VERSION 5.8 ;
BUSBITCHARS "[]" ;
DIVIDERCHAR "/" ;
UNITS
    DATABASE MICRONS 1000 ;
END UNITS

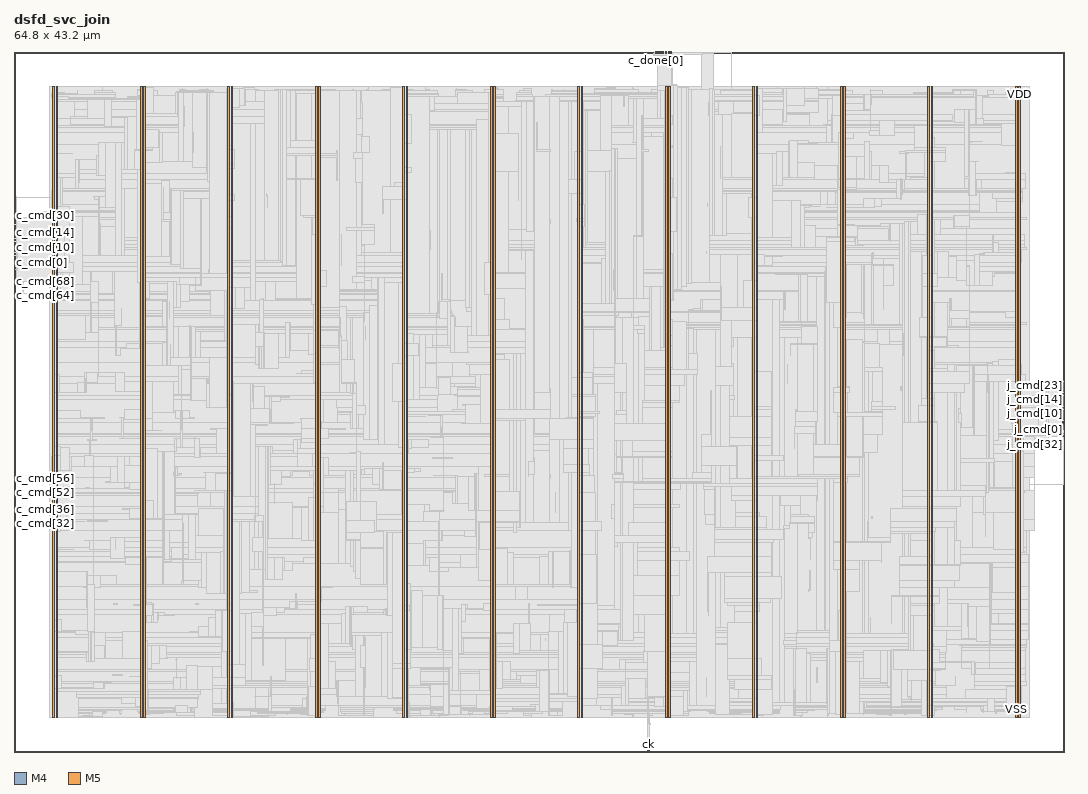
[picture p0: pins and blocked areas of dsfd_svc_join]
MACRO dsfd_svc_join
  FOREIGN dsfd_svc_join 0 0 ;
  CLASS BLOCK ;
  SIZE 64.8 BY 43.2 ;
  PIN c_cmd[0]
    DIRECTION INPUT ;
    USE SIGNAL ;
    PORT
      LAYER M4 ;
        RECT  0 30.192 0.084 30.216 ;
    END
  END c_cmd[0]
  PIN c_cmd[10]
    DIRECTION INPUT ;
    USE SIGNAL ;
    PORT
      LAYER M4 ;
        RECT  0 31.152 0.084 31.176 ;
    END
  END c_cmd[10]
  PIN c_cmd[11]
    DIRECTION INPUT ;
    USE SIGNAL ;
    PORT
      LAYER M4 ;
        RECT  0 31.248 0.084 31.272 ;
    END
  END c_cmd[11]
  PIN c_cmd[12]
    DIRECTION INPUT ;
    USE SIGNAL ;
    PORT
      LAYER M4 ;
        RECT  0 31.344 0.084 31.368 ;
    END
  END c_cmd[12]
  PIN c_cmd[13]
    DIRECTION INPUT ;
    USE SIGNAL ;
    PORT
      LAYER M4 ;
        RECT  0 31.44 0.084 31.464 ;
    END
  END c_cmd[13]
  PIN c_cmd[14]
    DIRECTION INPUT ;
    USE SIGNAL ;
    PORT
      LAYER M4 ;
        RECT  0 31.536 0.084 31.56 ;
    END
  END c_cmd[14]
  PIN c_cmd[15]
    DIRECTION INPUT ;
    USE SIGNAL ;
    PORT
      LAYER M4 ;
        RECT  0 31.632 0.084 31.656 ;
    END
  END c_cmd[15]
  PIN c_cmd[16]
    DIRECTION INPUT ;
    USE SIGNAL ;
    PORT
      LAYER M4 ;
        RECT  0 31.728 0.084 31.752 ;
    END
  END c_cmd[16]
  PIN c_cmd[17]
    DIRECTION INPUT ;
    USE SIGNAL ;
    PORT
      LAYER M4 ;
        RECT  0 31.824 0.084 31.848 ;
    END
  END c_cmd[17]
  PIN c_cmd[18]
    DIRECTION INPUT ;
    USE SIGNAL ;
    PORT
      LAYER M4 ;
        RECT  0 31.92 0.084 31.944 ;
    END
  END c_cmd[18]
  PIN c_cmd[19]
    DIRECTION INPUT ;
    USE SIGNAL ;
    PORT
      LAYER M4 ;
        RECT  0 32.016 0.084 32.04 ;
    END
  END c_cmd[19]
  PIN c_cmd[1]
    DIRECTION INPUT ;
    USE SIGNAL ;
    PORT
      LAYER M4 ;
        RECT  0 30.288 0.084 30.312 ;
    END
  END c_cmd[1]
  PIN c_cmd[20]
    DIRECTION INPUT ;
    USE SIGNAL ;
    PORT
      LAYER M4 ;
        RECT  0 32.112 0.084 32.136 ;
    END
  END c_cmd[20]
  PIN c_cmd[21]
    DIRECTION INPUT ;
    USE SIGNAL ;
    PORT
      LAYER M4 ;
        RECT  0 32.208 0.084 32.232 ;
    END
  END c_cmd[21]
  PIN c_cmd[22]
    DIRECTION INPUT ;
    USE SIGNAL ;
    PORT
      LAYER M4 ;
        RECT  0 32.304 0.084 32.328 ;
    END
  END c_cmd[22]
  PIN c_cmd[23]
    DIRECTION INPUT ;
    USE SIGNAL ;
    PORT
      LAYER M4 ;
        RECT  0 32.4 0.084 32.424 ;
    END
  END c_cmd[23]
  PIN c_cmd[24]
    DIRECTION INPUT ;
    USE SIGNAL ;
    PORT
      LAYER M4 ;
        RECT  0 32.496 0.084 32.52 ;
    END
  END c_cmd[24]
  PIN c_cmd[25]
    DIRECTION INPUT ;
    USE SIGNAL ;
    PORT
      LAYER M4 ;
        RECT  0 32.592 0.084 32.616 ;
    END
  END c_cmd[25]
  PIN c_cmd[26]
    DIRECTION INPUT ;
    USE SIGNAL ;
    PORT
      LAYER M4 ;
        RECT  0 32.688 0.084 32.712 ;
    END
  END c_cmd[26]
  PIN c_cmd[27]
    DIRECTION INPUT ;
    USE SIGNAL ;
    PORT
      LAYER M4 ;
        RECT  0 32.784 0.084 32.808 ;
    END
  END c_cmd[27]
  PIN c_cmd[28]
    DIRECTION INPUT ;
    USE SIGNAL ;
    PORT
      LAYER M4 ;
        RECT  0 32.88 0.084 32.904 ;
    END
  END c_cmd[28]
  PIN c_cmd[29]
    DIRECTION INPUT ;
    USE SIGNAL ;
    PORT
      LAYER M4 ;
        RECT  0 32.976 0.084 33 ;
    END
  END c_cmd[29]
  PIN c_cmd[2]
    DIRECTION INPUT ;
    USE SIGNAL ;
    PORT
      LAYER M4 ;
        RECT  0 30.384 0.084 30.408 ;
    END
  END c_cmd[2]
  PIN c_cmd[30]
    DIRECTION INPUT ;
    USE SIGNAL ;
    PORT
      LAYER M4 ;
        RECT  0 33.072 0.084 33.096 ;
    END
  END c_cmd[30]
  PIN c_cmd[31]
    DIRECTION INPUT ;
    USE SIGNAL ;
    PORT
      LAYER M4 ;
        RECT  0 33.168 0.084 33.192 ;
    END
  END c_cmd[31]
  PIN c_cmd[32]
    DIRECTION INPUT ;
    USE SIGNAL ;
    PORT
      LAYER M4 ;
        RECT  0 14.064 0.084 14.088 ;
    END
  END c_cmd[32]
  PIN c_cmd[33]
    DIRECTION INPUT ;
    USE SIGNAL ;
    PORT
      LAYER M4 ;
        RECT  0 14.16 0.084 14.184 ;
    END
  END c_cmd[33]
  PIN c_cmd[34]
    DIRECTION INPUT ;
    USE SIGNAL ;
    PORT
      LAYER M4 ;
        RECT  0 14.256 0.084 14.28 ;
    END
  END c_cmd[34]
  PIN c_cmd[35]
    DIRECTION INPUT ;
    USE SIGNAL ;
    PORT
      LAYER M4 ;
        RECT  0 14.352 0.084 14.376 ;
    END
  END c_cmd[35]
  PIN c_cmd[36]
    DIRECTION INPUT ;
    USE SIGNAL ;
    PORT
      LAYER M4 ;
        RECT  0 14.448 0.084 14.472 ;
    END
  END c_cmd[36]
  PIN c_cmd[37]
    DIRECTION INPUT ;
    USE SIGNAL ;
    PORT
      LAYER M4 ;
        RECT  0 14.544 0.084 14.568 ;
    END
  END c_cmd[37]
  PIN c_cmd[38]
    DIRECTION INPUT ;
    USE SIGNAL ;
    PORT
      LAYER M4 ;
        RECT  0 14.64 0.084 14.664 ;
    END
  END c_cmd[38]
  PIN c_cmd[39]
    DIRECTION INPUT ;
    USE SIGNAL ;
    PORT
      LAYER M4 ;
        RECT  0 14.736 0.084 14.76 ;
    END
  END c_cmd[39]
  PIN c_cmd[3]
    DIRECTION INPUT ;
    USE SIGNAL ;
    PORT
      LAYER M4 ;
        RECT  0 30.48 0.084 30.504 ;
    END
  END c_cmd[3]
  PIN c_cmd[40]
    DIRECTION INPUT ;
    USE SIGNAL ;
    PORT
      LAYER M4 ;
        RECT  0 14.832 0.084 14.856 ;
    END
  END c_cmd[40]
  PIN c_cmd[41]
    DIRECTION INPUT ;
    USE SIGNAL ;
    PORT
      LAYER M4 ;
        RECT  0 14.928 0.084 14.952 ;
    END
  END c_cmd[41]
  PIN c_cmd[42]
    DIRECTION INPUT ;
    USE SIGNAL ;
    PORT
      LAYER M4 ;
        RECT  0 15.024 0.084 15.048 ;
    END
  END c_cmd[42]
  PIN c_cmd[43]
    DIRECTION INPUT ;
    USE SIGNAL ;
    PORT
      LAYER M4 ;
        RECT  0 15.12 0.084 15.144 ;
    END
  END c_cmd[43]
  PIN c_cmd[44]
    DIRECTION INPUT ;
    USE SIGNAL ;
    PORT
      LAYER M4 ;
        RECT  0 15.216 0.084 15.24 ;
    END
  END c_cmd[44]
  PIN c_cmd[45]
    DIRECTION INPUT ;
    USE SIGNAL ;
    PORT
      LAYER M4 ;
        RECT  0 15.312 0.084 15.336 ;
    END
  END c_cmd[45]
  PIN c_cmd[46]
    DIRECTION INPUT ;
    USE SIGNAL ;
    PORT
      LAYER M4 ;
        RECT  0 15.408 0.084 15.432 ;
    END
  END c_cmd[46]
  PIN c_cmd[47]
    DIRECTION INPUT ;
    USE SIGNAL ;
    PORT
      LAYER M4 ;
        RECT  0 15.504 0.084 15.528 ;
    END
  END c_cmd[47]
  PIN c_cmd[48]
    DIRECTION INPUT ;
    USE SIGNAL ;
    PORT
      LAYER M4 ;
        RECT  0 15.6 0.084 15.624 ;
    END
  END c_cmd[48]
  PIN c_cmd[49]
    DIRECTION INPUT ;
    USE SIGNAL ;
    PORT
      LAYER M4 ;
        RECT  0 15.696 0.084 15.72 ;
    END
  END c_cmd[49]
  PIN c_cmd[4]
    DIRECTION INPUT ;
    USE SIGNAL ;
    PORT
      LAYER M4 ;
        RECT  0 30.576 0.084 30.6 ;
    END
  END c_cmd[4]
  PIN c_cmd[50]
    DIRECTION INPUT ;
    USE SIGNAL ;
    PORT
      LAYER M4 ;
        RECT  0 15.792 0.084 15.816 ;
    END
  END c_cmd[50]
  PIN c_cmd[51]
    DIRECTION INPUT ;
    USE SIGNAL ;
    PORT
      LAYER M4 ;
        RECT  0 15.888 0.084 15.912 ;
    END
  END c_cmd[51]
  PIN c_cmd[52]
    DIRECTION INPUT ;
    USE SIGNAL ;
    PORT
      LAYER M4 ;
        RECT  0 15.984 0.084 16.008 ;
    END
  END c_cmd[52]
  PIN c_cmd[53]
    DIRECTION INPUT ;
    USE SIGNAL ;
    PORT
      LAYER M4 ;
        RECT  0 16.08 0.084 16.104 ;
    END
  END c_cmd[53]
  PIN c_cmd[54]
    DIRECTION INPUT ;
    USE SIGNAL ;
    PORT
      LAYER M4 ;
        RECT  0 16.176 0.084 16.2 ;
    END
  END c_cmd[54]
  PIN c_cmd[55]
    DIRECTION INPUT ;
    USE SIGNAL ;
    PORT
      LAYER M4 ;
        RECT  0 16.272 0.084 16.296 ;
    END
  END c_cmd[55]
  PIN c_cmd[56]
    DIRECTION INPUT ;
    USE SIGNAL ;
    PORT
      LAYER M4 ;
        RECT  0 16.368 0.084 16.392 ;
    END
  END c_cmd[56]
  PIN c_cmd[57]
    DIRECTION INPUT ;
    USE SIGNAL ;
    PORT
      LAYER M4 ;
        RECT  0 16.464 0.084 16.488 ;
    END
  END c_cmd[57]
  PIN c_cmd[58]
    DIRECTION INPUT ;
    USE SIGNAL ;
    PORT
      LAYER M4 ;
        RECT  0 16.56 0.084 16.584 ;
    END
  END c_cmd[58]
  PIN c_cmd[59]
    DIRECTION INPUT ;
    USE SIGNAL ;
    PORT
      LAYER M4 ;
        RECT  0 16.656 0.084 16.68 ;
    END
  END c_cmd[59]
  PIN c_cmd[5]
    DIRECTION INPUT ;
    USE SIGNAL ;
    PORT
      LAYER M4 ;
        RECT  0 30.672 0.084 30.696 ;
    END
  END c_cmd[5]
  PIN c_cmd[60]
    DIRECTION INPUT ;
    USE SIGNAL ;
    PORT
      LAYER M4 ;
        RECT  0 16.752 0.084 16.776 ;
    END
  END c_cmd[60]
  PIN c_cmd[61]
    DIRECTION INPUT ;
    USE SIGNAL ;
    PORT
      LAYER M4 ;
        RECT  0 16.848 0.084 16.872 ;
    END
  END c_cmd[61]
  PIN c_cmd[62]
    DIRECTION INPUT ;
    USE SIGNAL ;
    PORT
      LAYER M4 ;
        RECT  0 16.944 0.084 16.968 ;
    END
  END c_cmd[62]
  PIN c_cmd[63]
    DIRECTION INPUT ;
    USE SIGNAL ;
    PORT
      LAYER M4 ;
        RECT  0 17.04 0.084 17.064 ;
    END
  END c_cmd[63]
  PIN c_cmd[64]
    DIRECTION INPUT ;
    USE SIGNAL ;
    PORT
      LAYER M4 ;
        RECT  0 28.176 0.084 28.2 ;
    END
  END c_cmd[64]
  PIN c_cmd[65]
    DIRECTION INPUT ;
    USE SIGNAL ;
    PORT
      LAYER M4 ;
        RECT  0 28.272 0.084 28.296 ;
    END
  END c_cmd[65]
  PIN c_cmd[66]
    DIRECTION INPUT ;
    USE SIGNAL ;
    PORT
      LAYER M4 ;
        RECT  0 28.368 0.084 28.392 ;
    END
  END c_cmd[66]
  PIN c_cmd[67]
    DIRECTION INPUT ;
    USE SIGNAL ;
    PORT
      LAYER M4 ;
        RECT  0 28.464 0.084 28.488 ;
    END
  END c_cmd[67]
  PIN c_cmd[68]
    DIRECTION INPUT ;
    USE SIGNAL ;
    PORT
      LAYER M4 ;
        RECT  0 28.56 0.084 28.584 ;
    END
  END c_cmd[68]
  PIN c_cmd[69]
    DIRECTION INPUT ;
    USE SIGNAL ;
    PORT
      LAYER M4 ;
        RECT  0 28.656 0.084 28.68 ;
    END
  END c_cmd[69]
  PIN c_cmd[6]
    DIRECTION INPUT ;
    USE SIGNAL ;
    PORT
      LAYER M4 ;
        RECT  0 30.768 0.084 30.792 ;
    END
  END c_cmd[6]
  PIN c_cmd[70]
    DIRECTION INPUT ;
    USE SIGNAL ;
    PORT
      LAYER M4 ;
        RECT  0 28.752 0.084 28.776 ;
    END
  END c_cmd[70]
  PIN c_cmd[71]
    DIRECTION INPUT ;
    USE SIGNAL ;
    PORT
      LAYER M4 ;
        RECT  0 28.848 0.084 28.872 ;
    END
  END c_cmd[71]
  PIN c_cmd[72]
    DIRECTION INPUT ;
    USE SIGNAL ;
    PORT
      LAYER M4 ;
        RECT  0 28.944 0.084 28.968 ;
    END
  END c_cmd[72]
  PIN c_cmd[73]
    DIRECTION INPUT ;
    USE SIGNAL ;
    PORT
      LAYER M4 ;
        RECT  0 29.04 0.084 29.064 ;
    END
  END c_cmd[73]
  PIN c_cmd[74]
    DIRECTION INPUT ;
    USE SIGNAL ;
    PORT
      LAYER M4 ;
        RECT  0 29.136 0.084 29.16 ;
    END
  END c_cmd[74]
  PIN c_cmd[75]
    DIRECTION INPUT ;
    USE SIGNAL ;
    PORT
      LAYER M4 ;
        RECT  0 29.232 0.084 29.256 ;
    END
  END c_cmd[75]
  PIN c_cmd[76]
    DIRECTION INPUT ;
    USE SIGNAL ;
    PORT
      LAYER M4 ;
        RECT  0 29.328 0.084 29.352 ;
    END
  END c_cmd[76]
  PIN c_cmd[77]
    DIRECTION INPUT ;
    USE SIGNAL ;
    PORT
      LAYER M4 ;
        RECT  0 29.424 0.084 29.448 ;
    END
  END c_cmd[77]
  PIN c_cmd[78]
    DIRECTION INPUT ;
    USE SIGNAL ;
    PORT
      LAYER M4 ;
        RECT  0 29.52 0.084 29.544 ;
    END
  END c_cmd[78]
  PIN c_cmd[79]
    DIRECTION INPUT ;
    USE SIGNAL ;
    PORT
      LAYER M4 ;
        RECT  0 29.616 0.084 29.64 ;
    END
  END c_cmd[79]
  PIN c_cmd[7]
    DIRECTION INPUT ;
    USE SIGNAL ;
    PORT
      LAYER M4 ;
        RECT  0 30.864 0.084 30.888 ;
    END
  END c_cmd[7]
  PIN c_cmd[80]
    DIRECTION INPUT ;
    USE SIGNAL ;
    PORT
      LAYER M4 ;
        RECT  0 29.712 0.084 29.736 ;
    END
  END c_cmd[80]
  PIN c_cmd[81]
    DIRECTION INPUT ;
    USE SIGNAL ;
    PORT
      LAYER M4 ;
        RECT  0 29.808 0.084 29.832 ;
    END
  END c_cmd[81]
  PIN c_cmd[82]
    DIRECTION INPUT ;
    USE SIGNAL ;
    PORT
      LAYER M4 ;
        RECT  0 29.904 0.084 29.928 ;
    END
  END c_cmd[82]
  PIN c_cmd[83]
    DIRECTION INPUT ;
    USE SIGNAL ;
    PORT
      LAYER M4 ;
        RECT  0 30 0.084 30.024 ;
    END
  END c_cmd[83]
  PIN c_cmd[84]
    DIRECTION INPUT ;
    USE SIGNAL ;
    PORT
      LAYER M4 ;
        RECT  0 30.096 0.084 30.12 ;
    END
  END c_cmd[84]
  PIN c_cmd[8]
    DIRECTION INPUT ;
    USE SIGNAL ;
    PORT
      LAYER M4 ;
        RECT  0 30.96 0.084 30.984 ;
    END
  END c_cmd[8]
  PIN c_cmd[9]
    DIRECTION INPUT ;
    USE SIGNAL ;
    PORT
      LAYER M4 ;
        RECT  0 31.056 0.084 31.08 ;
    END
  END c_cmd[9]
  PIN c_done[0]
    DIRECTION OUTPUT ;
    USE SIGNAL ;
    PORT
      LAYER M5 ;
        RECT  39.6 43.116 39.624 43.2 ;
    END
  END c_done[0]
  PIN c_done[1]
    DIRECTION OUTPUT ;
    USE SIGNAL ;
    PORT
      LAYER M5 ;
        RECT  39.696 43.116 39.72 43.2 ;
    END
  END c_done[1]
  PIN c_done[2]
    DIRECTION OUTPUT ;
    USE SIGNAL ;
    PORT
      LAYER M5 ;
        RECT  39.792 43.116 39.816 43.2 ;
    END
  END c_done[2]
  PIN c_done[3]
    DIRECTION OUTPUT ;
    USE SIGNAL ;
    PORT
      LAYER M5 ;
        RECT  39.888 43.116 39.912 43.2 ;
    END
  END c_done[3]
  PIN c_done[4]
    DIRECTION OUTPUT ;
    USE SIGNAL ;
    PORT
      LAYER M5 ;
        RECT  39.984 43.116 40.008 43.2 ;
    END
  END c_done[4]
  PIN c_done[5]
    DIRECTION OUTPUT ;
    USE SIGNAL ;
    PORT
      LAYER M5 ;
        RECT  40.08 43.116 40.104 43.2 ;
    END
  END c_done[5]
  PIN c_done[6]
    DIRECTION OUTPUT ;
    USE SIGNAL ;
    PORT
      LAYER M5 ;
        RECT  40.176 43.116 40.2 43.2 ;
    END
  END c_done[6]
  PIN c_done[7]
    DIRECTION OUTPUT ;
    USE SIGNAL ;
    PORT
      LAYER M5 ;
        RECT  40.272 43.116 40.296 43.2 ;
    END
  END c_done[7]
  PIN c_done[8]
    DIRECTION OUTPUT ;
    USE SIGNAL ;
    PORT
      LAYER M5 ;
        RECT  40.368 43.116 40.392 43.2 ;
    END
  END c_done[8]
  PIN c_st[0]
    DIRECTION OUTPUT ;
    USE SIGNAL ;
    PORT
      LAYER M5 ;
        RECT  40.464 43.116 40.488 43.2 ;
    END
  END c_st[0]
  PIN c_st[1]
    DIRECTION OUTPUT ;
    USE SIGNAL ;
    PORT
      LAYER M5 ;
        RECT  40.56 43.116 40.584 43.2 ;
    END
  END c_st[1]
  PIN ck
    DIRECTION INPUT ;
    USE SIGNAL ;
    PORT
      LAYER M5 ;
        RECT  39.12 0 39.144 0.084 ;
    END
  END ck
  PIN j_cmd[0]
    DIRECTION OUTPUT ;
    USE SIGNAL ;
    PORT
      LAYER M4 ;
        RECT  64.716 19.92 64.8 19.944 ;
    END
  END j_cmd[0]
  PIN j_cmd[10]
    DIRECTION OUTPUT ;
    USE SIGNAL ;
    PORT
      LAYER M4 ;
        RECT  64.716 20.88 64.8 20.904 ;
    END
  END j_cmd[10]
  PIN j_cmd[11]
    DIRECTION OUTPUT ;
    USE SIGNAL ;
    PORT
      LAYER M4 ;
        RECT  64.716 20.976 64.8 21 ;
    END
  END j_cmd[11]
  PIN j_cmd[12]
    DIRECTION OUTPUT ;
    USE SIGNAL ;
    PORT
      LAYER M4 ;
        RECT  64.716 21.072 64.8 21.096 ;
    END
  END j_cmd[12]
  PIN j_cmd[13]
    DIRECTION OUTPUT ;
    USE SIGNAL ;
    PORT
      LAYER M4 ;
        RECT  64.716 21.168 64.8 21.192 ;
    END
  END j_cmd[13]
  PIN j_cmd[14]
    DIRECTION OUTPUT ;
    USE SIGNAL ;
    PORT
      LAYER M4 ;
        RECT  64.716 21.264 64.8 21.288 ;
    END
  END j_cmd[14]
  PIN j_cmd[15]
    DIRECTION OUTPUT ;
    USE SIGNAL ;
    PORT
      LAYER M4 ;
        RECT  64.716 21.36 64.8 21.384 ;
    END
  END j_cmd[15]
  PIN j_cmd[16]
    DIRECTION OUTPUT ;
    USE SIGNAL ;
    PORT
      LAYER M4 ;
        RECT  64.716 21.456 64.8 21.48 ;
    END
  END j_cmd[16]
  PIN j_cmd[17]
    DIRECTION OUTPUT ;
    USE SIGNAL ;
    PORT
      LAYER M4 ;
        RECT  64.716 21.552 64.8 21.576 ;
    END
  END j_cmd[17]
  PIN j_cmd[18]
    DIRECTION OUTPUT ;
    USE SIGNAL ;
    PORT
      LAYER M4 ;
        RECT  64.716 21.648 64.8 21.672 ;
    END
  END j_cmd[18]
  PIN j_cmd[19]
    DIRECTION OUTPUT ;
    USE SIGNAL ;
    PORT
      LAYER M4 ;
        RECT  64.716 21.744 64.8 21.768 ;
    END
  END j_cmd[19]
  PIN j_cmd[1]
    DIRECTION OUTPUT ;
    USE SIGNAL ;
    PORT
      LAYER M4 ;
        RECT  64.716 20.016 64.8 20.04 ;
    END
  END j_cmd[1]
  PIN j_cmd[20]
    DIRECTION OUTPUT ;
    USE SIGNAL ;
    PORT
      LAYER M4 ;
        RECT  64.716 21.84 64.8 21.864 ;
    END
  END j_cmd[20]
  PIN j_cmd[21]
    DIRECTION OUTPUT ;
    USE SIGNAL ;
    PORT
      LAYER M4 ;
        RECT  64.716 21.936 64.8 21.96 ;
    END
  END j_cmd[21]
  PIN j_cmd[22]
    DIRECTION OUTPUT ;
    USE SIGNAL ;
    PORT
      LAYER M4 ;
        RECT  64.716 22.032 64.8 22.056 ;
    END
  END j_cmd[22]
  PIN j_cmd[23]
    DIRECTION OUTPUT ;
    USE SIGNAL ;
    PORT
      LAYER M4 ;
        RECT  64.716 22.128 64.8 22.152 ;
    END
  END j_cmd[23]
  PIN j_cmd[24]
    DIRECTION OUTPUT ;
    USE SIGNAL ;
    PORT
      LAYER M4 ;
        RECT  64.716 22.224 64.8 22.248 ;
    END
  END j_cmd[24]
  PIN j_cmd[25]
    DIRECTION OUTPUT ;
    USE SIGNAL ;
    PORT
      LAYER M4 ;
        RECT  64.716 22.32 64.8 22.344 ;
    END
  END j_cmd[25]
  PIN j_cmd[26]
    DIRECTION OUTPUT ;
    USE SIGNAL ;
    PORT
      LAYER M4 ;
        RECT  64.716 22.416 64.8 22.44 ;
    END
  END j_cmd[26]
  PIN j_cmd[27]
    DIRECTION OUTPUT ;
    USE SIGNAL ;
    PORT
      LAYER M4 ;
        RECT  64.716 22.512 64.8 22.536 ;
    END
  END j_cmd[27]
  PIN j_cmd[28]
    DIRECTION OUTPUT ;
    USE SIGNAL ;
    PORT
      LAYER M4 ;
        RECT  64.716 22.608 64.8 22.632 ;
    END
  END j_cmd[28]
  PIN j_cmd[29]
    DIRECTION OUTPUT ;
    USE SIGNAL ;
    PORT
      LAYER M4 ;
        RECT  64.716 22.704 64.8 22.728 ;
    END
  END j_cmd[29]
  PIN j_cmd[2]
    DIRECTION OUTPUT ;
    USE SIGNAL ;
    PORT
      LAYER M4 ;
        RECT  64.716 20.112 64.8 20.136 ;
    END
  END j_cmd[2]
  PIN j_cmd[30]
    DIRECTION OUTPUT ;
    USE SIGNAL ;
    PORT
      LAYER M4 ;
        RECT  64.716 22.8 64.8 22.824 ;
    END
  END j_cmd[30]
  PIN j_cmd[31]
    DIRECTION OUTPUT ;
    USE SIGNAL ;
    PORT
      LAYER M4 ;
        RECT  64.716 22.896 64.8 22.92 ;
    END
  END j_cmd[31]
  PIN j_cmd[32]
    DIRECTION OUTPUT ;
    USE SIGNAL ;
    PORT
      LAYER M4 ;
        RECT  64.716 19.44 64.8 19.464 ;
    END
  END j_cmd[32]
  PIN j_cmd[3]
    DIRECTION OUTPUT ;
    USE SIGNAL ;
    PORT
      LAYER M4 ;
        RECT  64.716 20.208 64.8 20.232 ;
    END
  END j_cmd[3]
  PIN j_cmd[4]
    DIRECTION OUTPUT ;
    USE SIGNAL ;
    PORT
      LAYER M4 ;
        RECT  64.716 20.304 64.8 20.328 ;
    END
  END j_cmd[4]
  PIN j_cmd[5]
    DIRECTION OUTPUT ;
    USE SIGNAL ;
    PORT
      LAYER M4 ;
        RECT  64.716 20.4 64.8 20.424 ;
    END
  END j_cmd[5]
  PIN j_cmd[6]
    DIRECTION OUTPUT ;
    USE SIGNAL ;
    PORT
      LAYER M4 ;
        RECT  64.716 20.496 64.8 20.52 ;
    END
  END j_cmd[6]
  PIN j_cmd[7]
    DIRECTION OUTPUT ;
    USE SIGNAL ;
    PORT
      LAYER M4 ;
        RECT  64.716 20.592 64.8 20.616 ;
    END
  END j_cmd[7]
  PIN j_cmd[8]
    DIRECTION OUTPUT ;
    USE SIGNAL ;
    PORT
      LAYER M4 ;
        RECT  64.716 20.688 64.8 20.712 ;
    END
  END j_cmd[8]
  PIN j_cmd[9]
    DIRECTION OUTPUT ;
    USE SIGNAL ;
    PORT
      LAYER M4 ;
        RECT  64.716 20.784 64.8 20.808 ;
    END
  END j_cmd[9]
  PIN j_dn[0]
    DIRECTION INPUT ;
    USE SIGNAL ;
    PORT
      LAYER M4 ;
        RECT  64.716 19.536 64.8 19.56 ;
    END
  END j_dn[0]
  PIN j_dn[1]
    DIRECTION INPUT ;
    USE SIGNAL ;
    PORT
      LAYER M4 ;
        RECT  64.716 19.632 64.8 19.656 ;
    END
  END j_dn[1]
  PIN rst
    DIRECTION INPUT ;
    USE SIGNAL ;
    PORT
      LAYER M5 ;
        RECT  39.216 0 39.24 0.084 ;
    END
  END rst
  PIN VDD
    DIRECTION INOUT ;
    USE POWER ;
    PORT
      LAYER M5 ;
        RECT  61.992 2.151 62.112 41.049 ;
        RECT  56.592 2.151 56.712 41.049 ;
        RECT  51.192 2.151 51.312 41.049 ;
        RECT  45.792 2.151 45.912 41.049 ;
        RECT  40.392 2.151 40.512 41.049 ;
        RECT  34.992 2.151 35.112 41.049 ;
        RECT  29.592 2.151 29.712 41.049 ;
        RECT  24.192 2.151 24.312 41.049 ;
        RECT  18.792 2.151 18.912 41.049 ;
        RECT  13.392 2.151 13.512 41.049 ;
        RECT  7.992 2.151 8.112 41.049 ;
        RECT  2.592 2.151 2.712 41.049 ;
    END
  END VDD
  PIN VSS
    DIRECTION INOUT ;
    USE GROUND ;
    PORT
      LAYER M5 ;
        RECT  61.8 2.137 61.92 41.063 ;
        RECT  56.4 2.137 56.52 41.063 ;
        RECT  51 2.137 51.12 41.063 ;
        RECT  45.6 2.137 45.72 41.063 ;
        RECT  40.2 2.137 40.32 41.063 ;
        RECT  34.8 2.137 34.92 41.063 ;
        RECT  29.4 2.137 29.52 41.063 ;
        RECT  24 2.137 24.12 41.063 ;
        RECT  18.6 2.137 18.72 41.063 ;
        RECT  13.2 2.137 13.32 41.063 ;
        RECT  7.8 2.137 7.92 41.063 ;
        RECT  2.4 2.137 2.52 41.063 ;
    END
  END VSS
  OBS
    LAYER RVTN ;
     RECT  2.16 2.16 62.64 2.295 ;
     RECT  2.16 2.565 62.64 2.835 ;
     RECT  2.16 3.105 62.64 3.375 ;
     RECT  2.16 3.645 62.64 3.915 ;
     RECT  2.16 4.185 62.64 4.455 ;
     RECT  2.16 4.725 62.64 4.995 ;
     RECT  2.16 5.265 62.64 5.535 ;
     RECT  2.16 5.805 62.64 6.075 ;
     RECT  2.16 6.345 62.64 6.615 ;
     RECT  2.16 6.885 62.64 7.155 ;
     RECT  2.16 7.425 62.64 7.695 ;
     RECT  2.16 7.965 62.64 8.235 ;
     RECT  2.16 8.505 62.64 8.775 ;
     RECT  2.16 9.045 62.64 9.315 ;
     RECT  2.16 9.585 62.64 9.855 ;
     RECT  2.16 10.125 62.64 10.395 ;
     RECT  2.16 10.665 62.64 10.935 ;
     RECT  2.16 11.205 62.64 11.475 ;
     RECT  2.16 11.745 62.64 12.015 ;
     RECT  2.16 12.285 62.64 12.555 ;
     RECT  2.16 12.825 62.64 13.095 ;
     RECT  2.16 13.365 62.64 13.635 ;
     RECT  2.16 13.905 62.64 14.175 ;
     RECT  2.16 14.445 62.64 14.715 ;
     RECT  2.16 14.985 62.64 15.255 ;
     RECT  2.16 15.525 62.64 15.795 ;
     RECT  2.16 16.065 62.64 16.335 ;
     RECT  2.16 16.605 62.64 16.875 ;
     RECT  2.16 17.145 62.64 17.415 ;
     RECT  2.16 17.685 62.64 17.955 ;
     RECT  2.16 18.225 62.64 18.495 ;
     RECT  2.16 18.765 62.64 19.035 ;
     RECT  2.16 19.305 62.64 19.575 ;
     RECT  2.16 19.845 62.64 20.115 ;
     RECT  2.16 20.385 62.64 20.655 ;
     RECT  2.16 20.925 62.64 21.195 ;
     RECT  2.16 21.465 62.64 21.735 ;
     RECT  2.16 22.005 62.64 22.275 ;
     RECT  2.16 22.545 62.64 22.815 ;
     RECT  2.16 23.085 62.64 23.355 ;
     RECT  2.16 23.625 62.64 23.895 ;
     RECT  2.16 24.165 62.64 24.435 ;
     RECT  2.16 24.705 62.64 24.975 ;
     RECT  2.16 25.245 62.64 25.515 ;
     RECT  2.16 25.785 62.64 26.055 ;
     RECT  2.16 26.325 62.64 26.595 ;
     RECT  2.16 26.865 62.64 27.135 ;
     RECT  2.16 27.405 62.64 27.675 ;
     RECT  2.16 27.945 62.64 28.215 ;
     RECT  2.16 28.485 62.64 28.755 ;
     RECT  2.16 29.025 62.64 29.295 ;
     RECT  2.16 29.565 62.64 29.835 ;
     RECT  2.16 30.105 62.64 30.375 ;
     RECT  2.16 30.645 62.64 30.915 ;
     RECT  2.16 31.185 62.64 31.455 ;
     RECT  2.16 31.725 62.64 31.995 ;
     RECT  2.16 32.265 62.64 32.535 ;
     RECT  2.16 32.805 62.64 33.075 ;
     RECT  2.16 33.345 62.64 33.615 ;
     RECT  2.16 33.885 62.64 34.155 ;
     RECT  2.16 34.425 62.64 34.695 ;
     RECT  2.16 34.965 62.64 35.235 ;
     RECT  2.16 35.505 62.64 35.775 ;
     RECT  2.16 36.045 62.64 36.315 ;
     RECT  2.16 36.585 62.64 36.855 ;
     RECT  2.16 37.125 62.64 37.395 ;
     RECT  2.16 37.665 62.64 37.935 ;
     RECT  2.16 38.205 62.64 38.475 ;
     RECT  2.16 38.745 62.64 39.015 ;
     RECT  2.16 39.285 62.64 39.555 ;
     RECT  2.16 39.825 62.64 40.095 ;
     RECT  2.16 40.365 62.64 40.635 ;
     RECT  2.16 40.905 62.64 41.04 ;
    LAYER RVTP ;
     RECT  2.16 2.295 62.64 2.565 ;
     RECT  2.16 2.835 62.64 3.105 ;
     RECT  2.16 3.375 62.64 3.645 ;
     RECT  2.16 3.915 62.64 4.185 ;
     RECT  2.16 4.455 62.64 4.725 ;
     RECT  2.16 4.995 62.64 5.265 ;
     RECT  2.16 5.535 62.64 5.805 ;
     RECT  2.16 6.075 62.64 6.345 ;
     RECT  2.16 6.615 62.64 6.885 ;
     RECT  2.16 7.155 62.64 7.425 ;
     RECT  2.16 7.695 62.64 7.965 ;
     RECT  2.16 8.235 62.64 8.505 ;
     RECT  2.16 8.775 62.64 9.045 ;
     RECT  2.16 9.315 62.64 9.585 ;
     RECT  2.16 9.855 62.64 10.125 ;
     RECT  2.16 10.395 62.64 10.665 ;
     RECT  2.16 10.935 62.64 11.205 ;
     RECT  2.16 11.475 62.64 11.745 ;
     RECT  2.16 12.015 62.64 12.285 ;
     RECT  2.16 12.555 62.64 12.825 ;
     RECT  2.16 13.095 62.64 13.365 ;
     RECT  2.16 13.635 62.64 13.905 ;
     RECT  2.16 14.175 62.64 14.445 ;
     RECT  2.16 14.715 62.64 14.985 ;
     RECT  2.16 15.255 62.64 15.525 ;
     RECT  2.16 15.795 62.64 16.065 ;
     RECT  2.16 16.335 62.64 16.605 ;
     RECT  2.16 16.875 62.64 17.145 ;
     RECT  2.16 17.415 62.64 17.685 ;
     RECT  2.16 17.955 62.64 18.225 ;
     RECT  2.16 18.495 62.64 18.765 ;
     RECT  2.16 19.035 62.64 19.305 ;
     RECT  2.16 19.575 62.64 19.845 ;
     RECT  2.16 20.115 62.64 20.385 ;
     RECT  2.16 20.655 62.64 20.925 ;
     RECT  2.16 21.195 62.64 21.465 ;
     RECT  2.16 21.735 62.64 22.005 ;
     RECT  2.16 22.275 62.64 22.545 ;
     RECT  2.16 22.815 62.64 23.085 ;
     RECT  2.16 23.355 62.64 23.625 ;
     RECT  2.16 23.895 62.64 24.165 ;
     RECT  2.16 24.435 62.64 24.705 ;
     RECT  2.16 24.975 62.64 25.245 ;
     RECT  2.16 25.515 62.64 25.785 ;
     RECT  2.16 26.055 62.64 26.325 ;
     RECT  2.16 26.595 62.64 26.865 ;
     RECT  2.16 27.135 62.64 27.405 ;
     RECT  2.16 27.675 62.64 27.945 ;
     RECT  2.16 28.215 62.64 28.485 ;
     RECT  2.16 28.755 62.64 29.025 ;
     RECT  2.16 29.295 62.64 29.565 ;
     RECT  2.16 29.835 62.64 30.105 ;
     RECT  2.16 30.375 62.64 30.645 ;
     RECT  2.16 30.915 62.64 31.185 ;
     RECT  2.16 31.455 62.64 31.725 ;
     RECT  2.16 31.995 62.64 32.265 ;
     RECT  2.16 32.535 62.64 32.805 ;
     RECT  2.16 33.075 62.64 33.345 ;
     RECT  2.16 33.615 62.64 33.885 ;
     RECT  2.16 34.155 62.64 34.425 ;
     RECT  2.16 34.695 62.64 34.965 ;
     RECT  2.16 35.235 62.64 35.505 ;
     RECT  2.16 35.775 62.64 36.045 ;
     RECT  2.16 36.315 62.64 36.585 ;
     RECT  2.16 36.855 62.64 37.125 ;
     RECT  2.16 37.395 62.64 37.665 ;
     RECT  2.16 37.935 62.64 38.205 ;
     RECT  2.16 38.475 62.64 38.745 ;
     RECT  2.16 39.015 62.64 39.285 ;
     RECT  2.16 39.555 62.64 39.825 ;
     RECT  2.16 40.095 62.64 40.365 ;
     RECT  2.16 40.635 62.64 40.905 ;
    LAYER M1 ;
     RECT  2.16 2.151 62.64 41.049 ;
    LAYER M2 ;
     RECT  0.103 29.34 0.139 29.358 ;
     RECT  0.103 30.312 0.139 30.33 ;
     RECT  0.139 29.34 0.175 30.33 ;
     RECT  0.103 31.5 0.175 31.518 ;
     RECT  0.175 29.34 1.759 31.518 ;
     RECT  0.103 32.31 1.759 32.328 ;
     RECT  0.535 28.296 2.16 28.314 ;
     RECT  1.759 29.34 2.16 32.328 ;
     RECT  1.723 33.354 2.16 33.372 ;
     RECT  2.16 2.151 38.191 41.049 ;
     RECT  38.191 2.106 50.207 41.049 ;
     RECT  50.207 2.151 62.64 41.049 ;
     RECT  62.64 13.644 62.987 13.662 ;
     RECT  62.64 19.35 63.851 22.734 ;
     RECT  63.851 19.656 63.887 22.23 ;
     RECT  63.887 19.926 63.923 22.23 ;
     RECT  63.923 19.926 63.959 20.844 ;
     RECT  63.923 21.591 63.959 22.23 ;
     RECT  63.959 19.926 64.679 20.682 ;
     RECT  64.679 20.394 64.715 20.682 ;
     RECT  63.959 22.212 64.715 22.23 ;
     RECT  62.64 16.506 64.787 16.524 ;
     RECT  64.715 20.664 64.787 20.682 ;
    LAYER M3 ;
     RECT  24.015 2.143 24.105 2.191 ;
     RECT  18.615 2.143 18.705 2.227 ;
     RECT  22.176 2.191 22.194 2.227 ;
     RECT  24.015 2.191 24.498 2.227 ;
     RECT  26.244 2.191 26.262 2.227 ;
     RECT  29.415 2.143 29.505 2.227 ;
     RECT  31.932 2.191 31.95 2.227 ;
     RECT  45.615 2.143 45.705 2.227 ;
     RECT  48.564 2.191 48.582 2.227 ;
     RECT  56.415 2.143 56.505 2.227 ;
     RECT  18.396 2.227 18.705 2.251 ;
     RECT  21.744 2.227 22.194 2.251 ;
     RECT  26.244 2.227 26.802 2.251 ;
     RECT  33.804 2.227 33.822 2.251 ;
     RECT  41.616 2.227 41.634 2.251 ;
     RECT  48.564 2.227 48.654 2.251 ;
     RECT  56.268 2.227 56.505 2.251 ;
     RECT  10.044 2.227 10.062 2.263 ;
     RECT  11.124 2.191 11.142 2.263 ;
     RECT  12.276 2.227 12.294 2.263 ;
     RECT  13.215 2.143 13.305 2.263 ;
     RECT  14.076 2.203 14.094 2.263 ;
     RECT  15.696 2.203 15.714 2.263 ;
     RECT  39.204 1.723 39.222 2.263 ;
     RECT  50.184 2.101 50.202 2.263 ;
     RECT  7.815 2.143 7.905 2.299 ;
     RECT  28.116 2.227 28.134 2.299 ;
     RECT  38.196 2.101 38.214 2.299 ;
     RECT  45.615 2.227 46.278 2.299 ;
     RECT  51.015 2.143 51.105 2.299 ;
     RECT  54.072 2.251 54.09 2.299 ;
     RECT  18.108 2.251 18.705 2.335 ;
     RECT  37.872 2.299 38.214 2.335 ;
     RECT  53.352 2.299 54.09 2.335 ;
     RECT  55.044 2.299 55.062 2.335 ;
     RECT  3.996 2.191 4.662 2.371 ;
     RECT  5.436 2.203 5.454 2.371 ;
     RECT  6.552 2.299 6.57 2.371 ;
     RECT  7.815 2.299 8.334 2.371 ;
     RECT  15.696 2.263 16.11 2.371 ;
     RECT  16.884 2.335 16.902 2.371 ;
     RECT  17.676 2.335 18.705 2.371 ;
     RECT  20.376 2.251 20.394 2.371 ;
     RECT  21.564 2.251 22.194 2.371 ;
     RECT  24.015 2.227 25.11 2.371 ;
     RECT  25.884 2.251 26.802 2.371 ;
     RECT  28.044 2.299 28.134 2.371 ;
     RECT  29.376 2.227 29.505 2.371 ;
     RECT  31.464 2.227 31.95 2.371 ;
     RECT  36.9 2.251 36.918 2.371 ;
     RECT  37.692 2.335 38.214 2.371 ;
     RECT  39.204 2.263 39.402 2.371 ;
     RECT  40.215 2.143 40.305 2.371 ;
     RECT  41.22 2.251 41.634 2.371 ;
     RECT  43.308 2.299 43.326 2.371 ;
     RECT  44.712 2.299 44.73 2.371 ;
     RECT  45.615 2.299 46.818 2.371 ;
     RECT  50.184 2.263 50.238 2.371 ;
     RECT  50.976 2.299 51.105 2.371 ;
     RECT  52.416 2.335 52.434 2.371 ;
     RECT  53.244 2.335 54.09 2.371 ;
     RECT  54.972 2.335 55.062 2.371 ;
     RECT  56.016 2.251 56.505 2.371 ;
     RECT  61.815 2.143 61.905 2.371 ;
     RECT  2.415 2.143 2.505 2.413 ;
     RECT  12.276 2.263 13.305 2.413 ;
     RECT  14.076 2.263 14.274 2.413 ;
     RECT  15.012 2.371 18.738 2.413 ;
     RECT  34.815 2.143 34.905 2.413 ;
     RECT  52.416 2.371 56.505 2.413 ;
     RECT  7.668 2.371 9.234 2.443 ;
     RECT  10.044 2.263 11.142 2.443 ;
     RECT  3.996 2.371 5.634 2.461 ;
     RECT  15.012 2.413 18.897 2.461 ;
     RECT  42.912 2.371 44.874 2.461 ;
     RECT  45.615 2.371 47.214 2.461 ;
     RECT  48.132 2.251 48.654 2.461 ;
     RECT  31.464 2.371 32.598 2.491 ;
     RECT  33.552 2.251 33.822 2.491 ;
     RECT  60.588 2.371 60.606 2.491 ;
     RECT  61.776 2.371 62.19 2.491 ;
     RECT  7.668 2.443 11.142 2.497 ;
     RECT  12.276 2.413 14.274 2.497 ;
     RECT  15.012 2.461 19.098 2.497 ;
     RECT  20.196 2.371 22.194 2.497 ;
     RECT  28.044 2.371 28.278 2.497 ;
     RECT  29.052 2.371 30.438 2.497 ;
     RECT  31.464 2.491 33.822 2.497 ;
     RECT  36.9 2.371 41.634 2.497 ;
     RECT  42.912 2.461 47.214 2.497 ;
     RECT  52.416 2.413 56.697 2.497 ;
     RECT  59.832 2.461 59.85 2.497 ;
     RECT  3.996 2.461 5.706 2.533 ;
     RECT  6.48 2.371 6.606 2.533 ;
     RECT  48.132 2.461 48.978 2.533 ;
     RECT  52.344 2.497 56.697 2.533 ;
     RECT  59.724 2.497 59.85 2.533 ;
     RECT  60.588 2.491 62.19 2.533 ;
     RECT  12.276 2.497 19.098 2.569 ;
     RECT  23.58 2.371 25.11 2.569 ;
     RECT  25.848 2.371 26.802 2.569 ;
     RECT  28.044 2.497 33.822 2.569 ;
     RECT  36.9 2.497 41.778 2.569 ;
     RECT  42.768 2.497 47.214 2.569 ;
     RECT  50.184 2.371 51.534 2.569 ;
     RECT  52.344 2.533 56.934 2.569 ;
     RECT  3.996 2.533 6.606 2.605 ;
     RECT  7.596 2.497 11.142 2.605 ;
     RECT  12.276 2.569 19.206 2.605 ;
     RECT  20.124 2.497 22.194 2.605 ;
     RECT  36.9 2.569 47.214 2.605 ;
     RECT  50.184 2.569 56.934 2.605 ;
     RECT  59.724 2.533 62.19 2.605 ;
     RECT  23.4 2.569 25.11 2.641 ;
     RECT  25.848 2.569 26.874 2.641 ;
     RECT  27.756 2.569 33.822 2.641 ;
     RECT  48.132 2.533 49.41 2.641 ;
     RECT  50.184 2.605 57.294 2.641 ;
     RECT  58.752 2.461 58.77 2.641 ;
     RECT  59.652 2.605 62.19 2.641 ;
     RECT  12.276 2.605 19.242 2.669 ;
     RECT  23.4 2.641 33.822 2.669 ;
     RECT  3.996 2.605 11.142 2.725 ;
     RECT  20.124 2.605 22.266 2.731 ;
     RECT  23.4 2.669 28.566 2.731 ;
     RECT  48.132 2.641 57.294 2.731 ;
     RECT  48.096 2.731 57.294 2.827 ;
     RECT  58.068 2.641 58.77 2.827 ;
     RECT  59.652 2.641 62.514 2.831 ;
     RECT  34.815 2.413 35.097 2.839 ;
     RECT  36.216 2.605 47.322 2.839 ;
     RECT  48.096 2.827 58.77 2.839 ;
     RECT  59.652 2.831 62.19 2.839 ;
     RECT  15.696 2.669 19.242 2.875 ;
     RECT  20.124 2.731 28.566 2.875 ;
     RECT  34.776 2.839 35.37 3.037 ;
     RECT  36.216 2.839 62.19 3.037 ;
     RECT  29.376 2.669 33.822 3.145 ;
     RECT  34.776 3.037 62.19 3.145 ;
     RECT  29.376 3.145 62.19 3.299 ;
     RECT  3.996 2.725 11.322 3.307 ;
     RECT  3.996 3.307 11.358 3.379 ;
     RECT  3.852 3.379 11.358 3.541 ;
     RECT  15.696 2.875 28.566 3.577 ;
     RECT  29.376 3.299 57.546 3.577 ;
     RECT  2.415 2.413 2.697 3.721 ;
     RECT  3.852 3.541 11.538 3.721 ;
     RECT  58.716 3.299 62.19 3.839 ;
     RECT  12.276 2.669 14.886 3.991 ;
     RECT  15.696 3.577 57.546 3.991 ;
     RECT  12.276 3.991 57.546 4.081 ;
     RECT  59.256 3.839 62.19 4.081 ;
     RECT  12.276 4.081 58.122 4.109 ;
     RECT  2.415 3.721 11.538 4.225 ;
     RECT  12.276 4.109 56.862 4.225 ;
     RECT  2.415 4.225 56.862 4.379 ;
     RECT  59.256 4.081 62.514 4.379 ;
     RECT  58.104 4.109 58.122 4.649 ;
     RECT  59.256 4.379 62.442 4.792 ;
     RECT  2.415 4.379 54.558 4.991 ;
     RECT  55.296 4.379 56.862 4.999 ;
     RECT  55.296 4.999 57.186 5.071 ;
     RECT  2.415 4.991 54.306 5.117 ;
     RECT  55.296 5.071 57.51 5.131 ;
     RECT  59.112 4.792 62.442 5.161 ;
     RECT  55.044 5.131 57.51 5.809 ;
     RECT  2.415 5.117 54.09 5.845 ;
     RECT  54.864 5.809 57.51 5.845 ;
     RECT  2.415 5.845 57.51 5.999 ;
     RECT  5.544 5.999 57.51 6.151 ;
     RECT  2.415 5.999 4.77 6.179 ;
     RECT  58.5 5.161 62.442 6.241 ;
     RECT  58.464 6.241 62.442 6.421 ;
     RECT  5.544 6.151 57.546 6.539 ;
     RECT  58.464 6.421 62.514 6.547 ;
     RECT  57.528 6.539 57.546 6.619 ;
     RECT  58.32 6.547 62.514 6.619 ;
     RECT  5.544 6.539 56.754 6.719 ;
     RECT  57.528 6.619 62.514 6.961 ;
     RECT  2.415 6.179 4.734 7.051 ;
     RECT  5.544 6.719 56.697 7.051 ;
     RECT  2.415 7.051 56.697 7.349 ;
     RECT  33.948 7.349 56.697 7.501 ;
     RECT  57.528 6.961 62.586 7.501 ;
     RECT  33.948 7.501 62.586 7.889 ;
     RECT  34.74 7.889 62.586 7.961 ;
     RECT  2.415 7.349 33.066 8.509 ;
     RECT  33.948 7.889 34.002 8.509 ;
     RECT  2.415 8.509 34.002 8.815 ;
     RECT  34.74 7.961 57.474 8.815 ;
     RECT  58.212 7.961 62.586 8.815 ;
     RECT  2.415 8.815 62.586 9.383 ;
     RECT  2.415 9.383 30.942 10.201 ;
     RECT  31.68 9.383 62.586 10.201 ;
     RECT  2.415 10.201 62.586 11.705 ;
     RECT  2.415 11.705 9.738 11.741 ;
     RECT  2.415 11.741 9.702 12.055 ;
     RECT  10.476 11.705 62.586 12.209 ;
     RECT  2.412 12.055 9.702 12.353 ;
     RECT  2.415 12.353 9.702 12.595 ;
     RECT  10.476 12.209 62.478 12.595 ;
     RECT  2.415 12.595 62.478 13.639 ;
     RECT  2.415 13.639 62.982 14.369 ;
     RECT  2.415 14.369 19.098 14.731 ;
     RECT  2.376 14.731 19.098 15.179 ;
     RECT  2.376 15.179 11.322 15.799 ;
     RECT  2.34 15.799 11.322 15.961 ;
     RECT  2.34 15.961 11.394 16.033 ;
     RECT  12.132 15.179 19.098 16.033 ;
     RECT  20.016 14.369 62.982 16.157 ;
     RECT  2.34 16.033 19.098 16.267 ;
     RECT  20.016 16.157 62.097 16.267 ;
     RECT  2.34 16.267 62.097 16.915 ;
     RECT  62.964 16.157 62.982 16.915 ;
     RECT  2.34 16.915 62.982 17.609 ;
     RECT  2.34 17.609 17.478 18.221 ;
     RECT  2.415 18.221 17.478 18.391 ;
     RECT  18.432 17.609 62.982 18.391 ;
     RECT  2.415 18.391 62.982 18.967 ;
     RECT  2.376 18.967 62.982 19.499 ;
     RECT  2.415 19.499 62.982 19.579 ;
     RECT  63.828 19.345 63.846 19.579 ;
     RECT  2.415 19.579 63.846 19.651 ;
     RECT  64.764 16.501 64.782 19.921 ;
     RECT  2.415 19.651 63.882 20.345 ;
     RECT  64.656 19.921 64.782 20.687 ;
     RECT  64.656 20.687 64.71 20.717 ;
     RECT  19.944 20.345 63.882 20.821 ;
     RECT  64.692 20.717 64.71 21.005 ;
     RECT  19.944 20.821 63.954 21.029 ;
     RECT  27.036 21.029 63.954 21.155 ;
     RECT  19.944 21.029 26.118 21.235 ;
     RECT  2.415 20.345 19.098 21.775 ;
     RECT  19.872 21.235 26.118 21.775 ;
     RECT  27.36 21.155 63.954 21.965 ;
     RECT  2.415 21.775 26.118 22.009 ;
     RECT  27.36 21.965 63.846 22.009 ;
     RECT  27.18 22.009 63.846 22.343 ;
     RECT  60.156 22.343 63.846 22.445 ;
     RECT  64.692 22.207 64.71 22.541 ;
     RECT  63.252 22.445 63.846 22.649 ;
     RECT  63.756 22.649 63.846 22.739 ;
     RECT  2.415 22.009 26.226 22.747 ;
     RECT  27.18 22.343 59.274 22.747 ;
     RECT  63.756 22.739 63.81 22.829 ;
     RECT  63.756 22.829 63.774 22.925 ;
     RECT  2.415 22.747 59.274 23.189 ;
     RECT  60.156 22.445 62.442 23.279 ;
     RECT  28.08 23.189 59.274 23.323 ;
     RECT  60.156 23.279 62.19 23.323 ;
     RECT  28.08 23.323 62.19 23.927 ;
     RECT  28.08 23.927 62.097 23.935 ;
     RECT  2.415 23.189 27.09 24.061 ;
     RECT  27.9 23.935 62.097 24.061 ;
     RECT  2.415 24.061 62.097 24.971 ;
     RECT  2.415 24.971 53.298 25.313 ;
     RECT  54.036 24.971 62.097 25.321 ;
     RECT  2.415 25.313 53.262 26.095 ;
     RECT  54.036 25.321 62.118 26.095 ;
     RECT  2.415 26.095 62.118 26.189 ;
     RECT  2.415 26.189 37.206 26.249 ;
     RECT  37.944 26.189 62.118 26.321 ;
     RECT  38.124 26.321 62.118 26.401 ;
     RECT  38.124 26.401 62.514 26.519 ;
     RECT  2.415 26.249 27.234 26.789 ;
     RECT  28.26 26.249 37.206 26.941 ;
     RECT  2.415 26.789 27.162 26.969 ;
     RECT  2.415 26.969 27.09 27.059 ;
     RECT  28.26 26.941 37.314 27.139 ;
     RECT  38.124 26.519 62.097 27.139 ;
     RECT  28.26 27.139 62.097 27.175 ;
     RECT  2.415 27.059 26.982 27.239 ;
     RECT  2.415 27.239 26.946 27.877 ;
     RECT  2.376 27.877 26.946 27.949 ;
     RECT  2.34 27.949 26.946 28.255 ;
     RECT  2.304 28.255 26.946 28.291 ;
     RECT  2.304 28.291 26.982 28.409 ;
     RECT  2.304 28.409 10.206 28.417 ;
     RECT  11.196 28.409 26.982 28.417 ;
     RECT  27.9 27.175 62.097 28.417 ;
     RECT  11.196 28.417 62.097 28.493 ;
     RECT  2.268 28.417 10.206 29.299 ;
     RECT  11.196 28.493 26.982 29.299 ;
     RECT  0.54 28.291 0.558 29.335 ;
     RECT  2.268 29.299 27.162 29.533 ;
     RECT  28.008 28.493 62.097 29.533 ;
     RECT  2.268 29.533 62.097 29.605 ;
     RECT  2.268 29.605 62.118 29.939 ;
     RECT  2.304 29.939 62.118 30.181 ;
     RECT  2.304 30.181 62.19 30.667 ;
     RECT  1.764 30.667 62.19 30.991 ;
     RECT  1.764 30.991 62.514 31.145 ;
     RECT  1.764 31.145 62.334 31.339 ;
     RECT  0.108 29.335 0.558 31.565 ;
     RECT  1.728 31.339 62.334 31.565 ;
     RECT  54.72 31.565 62.334 31.919 ;
     RECT  1.728 31.565 53.982 32.305 ;
     RECT  54.72 31.919 62.097 32.305 ;
     RECT  0.108 31.565 0.198 32.525 ;
     RECT  0.108 32.525 0.126 32.813 ;
     RECT  1.728 32.305 62.097 32.881 ;
     RECT  1.728 32.881 62.514 32.999 ;
     RECT  1.728 32.999 62.097 33.269 ;
     RECT  1.728 33.269 59.562 33.377 ;
     RECT  2.232 33.377 59.562 33.413 ;
     RECT  2.304 33.413 59.562 33.809 ;
     RECT  60.66 33.269 62.097 33.961 ;
     RECT  60.66 33.961 62.262 34.159 ;
     RECT  50.724 33.809 59.562 34.501 ;
     RECT  60.408 34.159 62.262 34.501 ;
     RECT  2.304 33.809 49.77 34.591 ;
     RECT  50.724 34.501 62.262 34.591 ;
     RECT  2.304 34.591 62.262 34.655 ;
     RECT  2.376 34.655 62.262 34.771 ;
     RECT  2.376 34.771 62.442 35.303 ;
     RECT  2.376 35.303 62.406 35.699 ;
     RECT  2.376 35.699 62.097 37.463 ;
     RECT  2.376 37.463 39.33 38.209 ;
     RECT  40.068 37.463 62.097 38.209 ;
     RECT  2.376 38.209 62.097 38.543 ;
     RECT  2.415 38.543 62.097 38.669 ;
     RECT  36.9 38.669 62.097 38.675 ;
     RECT  3.456 38.669 36.09 38.705 ;
     RECT  3.456 38.705 17.694 38.741 ;
     RECT  49.932 38.675 62.097 38.741 ;
     RECT  50.184 38.741 62.097 38.975 ;
     RECT  3.456 38.741 17.658 39.209 ;
     RECT  36.9 38.675 49.086 39.341 ;
     RECT  50.472 38.975 62.097 39.341 ;
     RECT  44.28 39.341 49.086 39.389 ;
     RECT  44.424 39.389 49.086 39.487 ;
     RECT  18.468 38.705 36.09 39.499 ;
     RECT  36.9 39.341 43.506 39.499 ;
     RECT  3.744 39.209 17.658 39.631 ;
     RECT  18.468 39.499 43.506 39.631 ;
     RECT  3.744 39.631 43.506 40.135 ;
     RECT  3.744 40.135 43.578 40.163 ;
     RECT  2.415 38.669 2.697 40.171 ;
     RECT  3.744 40.163 30.222 40.171 ;
     RECT  30.96 40.163 43.578 40.171 ;
     RECT  44.424 39.487 49.626 40.171 ;
     RECT  30.96 40.171 49.626 40.199 ;
     RECT  2.415 40.171 30.222 40.325 ;
     RECT  7.02 40.325 30.222 40.397 ;
     RECT  50.796 39.341 62.097 40.397 ;
     RECT  2.415 40.325 6.246 40.411 ;
     RECT  10.008 40.397 30.222 40.433 ;
     RECT  31.032 40.199 49.626 40.441 ;
     RECT  50.796 40.397 59.202 40.441 ;
     RECT  7.02 40.397 9.126 40.469 ;
     RECT  31.032 40.441 59.202 40.469 ;
     RECT  7.596 40.469 9.054 40.541 ;
     RECT  2.34 40.411 6.246 40.559 ;
     RECT  10.008 40.433 26.19 40.559 ;
     RECT  27.216 40.433 30.222 40.559 ;
     RECT  31.032 40.469 32.022 40.559 ;
     RECT  32.796 40.469 59.202 40.559 ;
     RECT  60.084 40.397 62.097 40.559 ;
     RECT  2.34 40.559 4.122 40.595 ;
     RECT  32.796 40.559 51.75 40.595 ;
     RECT  52.848 40.559 54.306 40.595 ;
     RECT  2.34 40.595 3.906 40.631 ;
     RECT  2.415 40.631 3.906 40.667 ;
     RECT  13.14 40.559 26.19 40.667 ;
     RECT  33.192 40.595 41.634 40.667 ;
     RECT  55.548 40.559 55.638 40.685 ;
     RECT  2.415 40.667 3.114 40.703 ;
     RECT  4.968 40.559 6.246 40.703 ;
     RECT  31.032 40.559 31.914 40.703 ;
     RECT  35.82 40.667 41.634 40.703 ;
     RECT  55.548 40.685 55.566 40.703 ;
     RECT  10.008 40.559 12.33 40.739 ;
     RECT  2.415 40.703 2.697 40.787 ;
     RECT  33.192 40.667 35.097 40.787 ;
     RECT  56.415 40.559 56.697 40.787 ;
     RECT  61.2 40.559 62.097 40.787 ;
     RECT  2.415 40.787 2.538 40.829 ;
     RECT  3.888 40.667 3.906 40.829 ;
     RECT  4.968 40.703 6.066 40.829 ;
     RECT  7.596 40.541 8.874 40.829 ;
     RECT  10.188 40.739 12.33 40.829 ;
     RECT  13.14 40.667 26.154 40.829 ;
     RECT  27.216 40.559 28.278 40.829 ;
     RECT  31.176 40.703 31.914 40.829 ;
     RECT  33.192 40.787 34.905 40.829 ;
     RECT  42.444 40.595 51.75 40.829 ;
     RECT  52.848 40.595 53.622 40.829 ;
     RECT  57.924 40.559 58.41 40.829 ;
     RECT  59.184 40.559 59.202 40.829 ;
     RECT  60.084 40.559 60.462 40.829 ;
     RECT  61.2 40.787 61.905 40.829 ;
     RECT  13.14 40.829 19.854 40.835 ;
     RECT  7.596 40.829 8.622 40.865 ;
     RECT  10.188 40.829 10.566 40.865 ;
     RECT  11.448 40.829 12.006 40.865 ;
     RECT  13.14 40.835 15.102 40.865 ;
     RECT  16.056 40.835 19.854 40.865 ;
     RECT  20.916 40.829 20.934 40.865 ;
     RECT  21.744 40.829 21.906 40.865 ;
     RECT  22.716 40.829 24.642 40.865 ;
     RECT  25.38 40.829 25.65 40.865 ;
     RECT  27.216 40.829 27.954 40.865 ;
     RECT  33.192 40.829 33.21 40.865 ;
     RECT  33.948 40.829 34.002 40.865 ;
     RECT  39.348 40.703 41.634 40.865 ;
     RECT  42.444 40.829 46.17 40.865 ;
     RECT  47.052 40.829 51.354 40.865 ;
     RECT  52.848 40.829 52.866 40.865 ;
     RECT  13.14 40.865 14.886 40.877 ;
     RECT  16.056 40.865 16.794 40.877 ;
     RECT  44.064 40.865 44.874 40.877 ;
     RECT  57.924 40.829 58.266 40.877 ;
     RECT  10.368 40.865 10.566 40.901 ;
     RECT  11.808 40.865 12.006 40.901 ;
     RECT  13.14 40.877 14.85 40.901 ;
     RECT  16.056 40.877 16.326 40.901 ;
     RECT  17.64 40.865 17.658 40.901 ;
     RECT  18.615 40.865 19.674 40.901 ;
     RECT  23.256 40.865 24.642 40.901 ;
     RECT  27.288 40.865 27.954 40.901 ;
     RECT  29.052 40.559 30.222 40.901 ;
     RECT  33.984 40.865 34.002 40.901 ;
     RECT  35.82 40.703 38.538 40.901 ;
     RECT  44.064 40.877 44.298 40.901 ;
     RECT  47.088 40.865 48.798 40.901 ;
     RECT  10.368 40.901 10.386 40.937 ;
     RECT  11.916 40.901 11.934 40.937 ;
     RECT  27.288 40.901 27.306 40.937 ;
     RECT  29.376 40.901 29.898 40.937 ;
     RECT  35.82 40.901 37.134 40.937 ;
     RECT  51.015 40.865 51.354 40.937 ;
     RECT  13.14 40.901 13.41 40.973 ;
     RECT  29.415 40.937 29.898 40.973 ;
     RECT  31.464 40.829 31.914 40.973 ;
     RECT  38.196 40.901 38.214 40.973 ;
     RECT  45.615 40.865 46.026 40.973 ;
     RECT  48.06 40.901 48.798 40.973 ;
     RECT  49.536 40.865 49.626 40.973 ;
     RECT  7.815 40.865 8.622 40.982 ;
     RECT  5.436 40.829 5.454 41.009 ;
     RECT  13.176 40.973 13.374 41.009 ;
     RECT  14.184 40.901 14.85 41.009 ;
     RECT  21.888 40.865 21.906 41.009 ;
     RECT  25.38 40.865 25.398 41.009 ;
     RECT  29.415 40.973 29.826 41.009 ;
     RECT  36.576 40.937 37.134 41.009 ;
     RECT  47.124 40.901 47.142 41.009 ;
     RECT  48.78 40.973 48.798 41.009 ;
     RECT  49.536 40.973 49.554 41.009 ;
     RECT  7.815 40.982 8.586 41.021 ;
     RECT  23.256 40.901 24.105 41.021 ;
     RECT  39.924 40.865 41.634 41.021 ;
     RECT  23.256 41.021 23.274 41.032 ;
     RECT  2.415 40.829 2.505 41.057 ;
     RECT  7.815 41.021 7.905 41.057 ;
     RECT  13.215 41.009 13.305 41.057 ;
     RECT  18.615 40.901 18.705 41.057 ;
     RECT  24.015 41.021 24.105 41.057 ;
     RECT  29.415 41.009 29.505 41.057 ;
     RECT  34.815 40.829 34.905 41.057 ;
     RECT  45.615 40.973 45.705 41.057 ;
     RECT  51.015 40.937 51.105 41.057 ;
     RECT  56.415 40.787 56.505 41.057 ;
     RECT  61.815 40.829 61.905 41.057 ;
     RECT  40.104 41.021 40.914 41.165 ;
     RECT  40.104 41.165 40.626 42.173 ;
     RECT  40.572 42.173 40.626 42.941 ;
     RECT  40.572 42.941 40.59 42.955 ;
     RECT  40.212 42.955 40.59 43.037 ;
     RECT  42.444 40.865 43.146 43.085 ;
     RECT  43.128 43.085 43.146 43.133 ;
     RECT  40.212 43.037 40.23 43.181 ;
     RECT  44.28 40.901 44.298 43.181 ;
    LAYER M4 ;
     RECT  0.06 30 0.133 33.096 ;
     RECT  0.133 29.04 0.179 33.096 ;
     RECT  2.365 14.736 2.408 14.76 ;
     RECT  2.365 16.368 2.408 16.392 ;
     RECT  0.179 29.04 2.408 33 ;
     RECT  0.133 34.224 2.408 34.248 ;
     RECT  2.365 35.424 2.408 35.448 ;
     RECT  2.365 36.912 2.408 36.936 ;
     RECT  2.329 40.416 2.408 40.44 ;
     RECT  2.408 2.148 2.512 41.052 ;
     RECT  2.512 2.418 2.704 40.782 ;
     RECT  2.704 23.232 2.819 23.256 ;
     RECT  2.704 17.376 2.867 18.84 ;
     RECT  2.704 13.632 2.873 14.76 ;
     RECT  2.704 28.128 2.873 35.448 ;
     RECT  2.704 3.936 2.915 4.68 ;
     RECT  2.704 7.44 2.915 8.184 ;
     RECT  2.704 15.792 2.981 16.392 ;
     RECT  2.873 28.848 3.017 35.448 ;
     RECT  2.873 14.208 3.233 14.76 ;
     RECT  2.704 40.272 3.377 40.44 ;
     RECT  3.017 28.848 3.443 33.672 ;
     RECT  2.867 17.376 3.449 18.792 ;
     RECT  2.981 16.368 3.485 16.392 ;
     RECT  3.449 17.376 3.521 18.264 ;
     RECT  2.704 36.912 3.593 36.936 ;
     RECT  2.704 12.48 3.665 12.504 ;
     RECT  2.915 7.44 3.805 7.512 ;
     RECT  3.017 34.8 3.805 35.448 ;
     RECT  2.704 22.176 3.913 22.2 ;
     RECT  3.805 34.8 3.953 36.552 ;
     RECT  3.953 35.136 4.025 36.552 ;
     RECT  2.704 20.592 4.097 21.096 ;
     RECT  3.443 28.848 4.205 33.048 ;
     RECT  3.913 22.176 4.337 22.824 ;
     RECT  4.337 22.176 4.381 23.016 ;
     RECT  3.233 14.208 4.385 14.232 ;
     RECT  2.704 25.44 4.385 26.952 ;
     RECT  3.521 17.616 4.403 18.264 ;
     RECT  4.309 10.128 4.46 10.152 ;
     RECT  4.46 9.648 4.461 10.152 ;
     RECT  2.704 11.136 4.461 11.16 ;
     RECT  2.704 6.144 4.489 6.168 ;
     RECT  4.381 22.176 4.493 23.4 ;
     RECT  4.461 9.648 4.501 11.16 ;
     RECT  2.704 39.072 4.525 39.096 ;
     RECT  3.377 40.272 4.525 40.296 ;
     RECT  4.501 8.928 4.547 11.16 ;
     RECT  4.547 10.128 4.565 11.16 ;
     RECT  4.547 8.928 4.588 8.952 ;
     RECT  4.489 5.616 4.597 6.168 ;
     RECT  3.805 7.248 4.597 7.512 ;
     RECT  4.403 18.24 4.633 18.264 ;
     RECT  4.525 19.248 4.633 19.272 ;
     RECT  4.417 16.272 4.637 16.296 ;
     RECT  4.381 13.056 4.669 13.08 ;
     RECT  4.385 25.872 4.693 26.952 ;
     RECT  4.693 25.872 4.705 27.768 ;
     RECT  4.205 28.848 4.705 29.64 ;
     RECT  4.597 5.616 4.709 7.512 ;
     RECT  4.633 18.24 4.741 19.272 ;
     RECT  4.097 20.592 4.741 20.616 ;
     RECT  4.741 18.24 4.745 20.616 ;
     RECT  4.705 25.872 4.78 29.64 ;
     RECT  4.709 5.616 4.781 7.464 ;
     RECT  4.78 25.872 4.781 26.856 ;
     RECT  4.745 19.248 4.828 20.616 ;
     RECT  4.201 2.208 4.849 2.232 ;
     RECT  2.915 3.936 4.921 3.96 ;
     RECT  4.745 18.24 4.969 18.264 ;
     RECT  4.781 5.616 4.979 7.368 ;
     RECT  4.921 34.272 4.993 34.296 ;
     RECT  4.025 35.952 5.065 36.552 ;
     RECT  5.065 35.568 5.101 36.552 ;
     RECT  4.828 19.248 5.105 19.272 ;
     RECT  4.493 22.8 5.177 23.4 ;
     RECT  4.205 30.624 5.209 33.048 ;
     RECT  4.993 34.08 5.209 34.296 ;
     RECT  5.101 35.568 5.209 36.84 ;
     RECT  4.781 25.872 5.219 26.808 ;
     RECT  5.209 35.568 5.245 37.08 ;
     RECT  5.209 30.624 5.285 34.296 ;
     RECT  5.285 30.624 5.315 32.616 ;
     RECT  4.565 10.128 5.357 10.872 ;
     RECT  4.849 2.208 5.465 2.52 ;
     RECT  4.828 20.592 5.573 20.616 ;
     RECT  4.921 3.936 5.596 4.296 ;
     RECT  4.525 39.072 5.605 40.296 ;
     RECT  5.285 33.6 5.641 34.296 ;
     RECT  5.245 35.568 5.641 37.608 ;
     RECT  4.979 5.76 5.645 7.368 ;
     RECT  5.465 2.496 5.717 2.52 ;
     RECT  4.525 14.256 5.789 14.28 ;
     RECT  4.669 12.48 5.929 13.08 ;
     RECT  5.677 16.656 5.965 16.68 ;
     RECT  5.596 4.272 6.041 4.296 ;
     RECT  5.605 38.592 6.041 40.296 ;
     RECT  4.78 28.32 6.073 29.64 ;
     RECT  5.219 26.208 6.181 26.808 ;
     RECT  6.073 28.272 6.181 29.64 ;
     RECT  5.177 23.184 6.253 23.4 ;
     RECT  5.315 30.624 6.289 32.424 ;
     RECT  5.641 33.6 6.289 37.608 ;
     RECT  5.357 10.32 6.329 10.872 ;
     RECT  5.965 16.656 6.361 17.64 ;
     RECT  6.145 9.12 6.401 9.144 ;
     RECT  6.277 24.48 6.545 24.936 ;
     RECT  6.541 19.344 6.649 19.368 ;
     RECT  6.541 20.64 6.649 20.664 ;
     RECT  6.289 30.624 6.653 37.608 ;
     RECT  5.645 5.76 6.685 6.888 ;
     RECT  6.073 4.752 6.689 4.776 ;
     RECT  6.649 19.344 6.761 20.664 ;
     RECT  6.361 16.656 6.793 18.264 ;
     RECT  6.653 30.624 6.797 34.776 ;
     RECT  6.761 20.544 6.829 20.664 ;
     RECT  6.653 35.952 6.829 37.608 ;
     RECT  6.041 38.592 6.829 39.144 ;
     RECT  5.929 11.952 6.833 13.224 ;
     RECT  6.253 22.224 6.833 23.4 ;
     RECT  6.833 11.952 6.901 11.976 ;
     RECT  6.545 24.912 6.937 24.936 ;
     RECT  6.829 35.952 7.009 39.144 ;
     RECT  6.793 16.32 7.117 18.264 ;
     RECT  6.721 14.976 7.153 15 ;
     RECT  6.613 3.024 7.513 3.336 ;
     RECT  7.009 35.952 7.585 39.24 ;
     RECT  6.041 40.272 7.585 40.296 ;
     RECT  6.937 24.912 7.765 25.224 ;
     RECT  6.181 26.208 7.765 29.64 ;
     RECT  7.513 2.784 7.808 3.336 ;
     RECT  7.153 4.656 7.808 4.68 ;
     RECT  6.685 5.76 7.808 7.464 ;
     RECT  7.369 9.072 7.808 9.096 ;
     RECT  6.329 10.32 7.808 10.344 ;
     RECT  6.901 11.568 7.808 11.976 ;
     RECT  6.833 13.008 7.808 13.224 ;
     RECT  7.153 14.4 7.808 15 ;
     RECT  7.117 16.176 7.808 18.264 ;
     RECT  6.761 19.344 7.808 19.368 ;
     RECT  6.829 20.544 7.808 21.144 ;
     RECT  6.833 22.224 7.808 22.872 ;
     RECT  7.765 24.912 7.808 29.64 ;
     RECT  6.797 30.624 7.808 30.648 ;
     RECT  6.797 31.728 7.808 34.776 ;
     RECT  7.585 35.952 7.808 40.296 ;
     RECT  7.808 2.148 7.912 41.052 ;
     RECT  7.912 2.418 8.104 41.016 ;
     RECT  8.104 8.016 8.201 11.976 ;
     RECT  8.104 2.592 8.243 6.888 ;
     RECT  8.243 2.592 8.273 3.864 ;
     RECT  8.104 27.984 8.381 29.016 ;
     RECT  8.243 5.184 8.489 6.552 ;
     RECT  8.201 8.016 8.489 9.24 ;
     RECT  8.104 19.824 8.531 22.872 ;
     RECT  8.489 8.016 8.597 9.144 ;
     RECT  8.104 39.408 8.597 41.016 ;
     RECT  8.104 14.4 8.849 18.744 ;
     RECT  8.597 8.016 8.885 8.616 ;
     RECT  8.885 8.16 8.921 8.616 ;
     RECT  8.104 36.384 8.956 38.376 ;
     RECT  8.489 5.472 8.957 6.552 ;
     RECT  8.104 30.576 9.097 35.064 ;
     RECT  8.531 19.824 9.101 19.848 ;
     RECT  8.104 13.056 9.157 13.08 ;
     RECT  8.849 14.4 9.157 18.552 ;
     RECT  8.201 10.32 9.169 11.976 ;
     RECT  9.157 13.056 9.169 18.552 ;
     RECT  8.104 23.856 9.169 25.224 ;
     RECT  8.104 26.256 9.169 26.856 ;
     RECT  8.956 36.384 9.173 38.232 ;
     RECT  9.169 10.32 9.209 18.552 ;
     RECT  8.921 8.448 9.281 8.616 ;
     RECT  9.209 11.904 9.281 18.552 ;
     RECT  9.169 23.856 9.385 25.272 ;
     RECT  9.169 26.256 9.385 27.816 ;
     RECT  8.957 5.76 9.389 6.552 ;
     RECT  9.389 5.76 9.425 6.36 ;
     RECT  9.385 23.856 9.457 27.816 ;
     RECT  8.381 28.896 9.457 29.016 ;
     RECT  9.425 5.76 9.461 5.784 ;
     RECT  9.281 11.904 9.569 13.656 ;
     RECT  9.097 30.576 9.605 35.256 ;
     RECT  9.605 30.576 9.637 34.776 ;
     RECT  9.637 30.096 9.713 34.776 ;
     RECT  8.273 3.84 9.817 3.864 ;
     RECT  8.531 20.976 9.821 22.872 ;
     RECT  8.273 2.592 9.853 2.664 ;
     RECT  9.457 23.856 9.857 29.016 ;
     RECT  9.281 14.64 9.889 18.552 ;
     RECT  9.281 8.448 9.893 8.472 ;
     RECT  9.853 2.496 9.925 2.664 ;
     RECT  9.889 14.64 9.929 19.368 ;
     RECT  9.929 14.64 9.965 17.544 ;
     RECT  9.925 2.448 9.997 2.664 ;
     RECT  9.821 20.976 9.997 21.096 ;
     RECT  8.597 39.408 9.997 40.536 ;
     RECT  9.929 18.528 10.001 19.368 ;
     RECT  9.857 27.408 10.037 29.016 ;
     RECT  9.965 17.04 10.073 17.544 ;
     RECT  9.997 5.712 10.081 5.736 ;
     RECT  9.997 39.408 10.105 40.728 ;
     RECT  9.821 22.08 10.177 22.872 ;
     RECT  9.857 23.856 10.177 26.28 ;
     RECT  9.173 36.432 10.177 38.232 ;
     RECT  10.105 39.312 10.177 40.728 ;
     RECT  10.073 17.04 10.217 17.16 ;
     RECT  9.817 3.84 10.253 4.584 ;
     RECT  10.001 18.768 10.285 19.368 ;
     RECT  9.997 20.592 10.285 21.096 ;
     RECT  9.713 30.096 10.285 34.68 ;
     RECT  10.037 27.408 10.289 28.824 ;
     RECT  10.217 17.136 10.325 17.16 ;
     RECT  9.209 10.32 10.364 10.344 ;
     RECT  10.285 18.768 10.369 21.096 ;
     RECT  9.569 12.912 10.405 13.656 ;
     RECT  9.965 14.64 10.405 14.664 ;
     RECT  10.285 29.808 10.433 34.68 ;
     RECT  10.177 36.432 10.433 40.728 ;
     RECT  10.364 10.32 10.45 10.536 ;
     RECT  10.253 3.888 10.645 4.584 ;
     RECT  9.997 2.448 10.685 2.856 ;
     RECT  9.569 11.904 10.789 11.928 ;
     RECT  10.405 12.912 10.789 14.664 ;
     RECT  10.369 20.592 10.829 21.096 ;
     RECT  10.289 27.792 10.835 28.824 ;
     RECT  10.685 2.448 10.865 2.76 ;
     RECT  10.177 22.08 10.897 26.28 ;
     RECT  10.897 21.696 10.924 26.28 ;
     RECT  10.865 2.496 10.937 2.76 ;
     RECT  10.433 36.432 11.005 40.68 ;
     RECT  10.937 2.688 11.045 2.76 ;
     RECT  10.369 18.768 11.125 19.368 ;
     RECT  11.125 18.72 11.149 19.368 ;
     RECT  10.829 20.592 11.153 20.616 ;
     RECT  10.789 11.904 11.189 14.664 ;
     RECT  10.924 24.336 11.189 26.28 ;
     RECT  10.645 3.888 11.297 5.352 ;
     RECT  10.861 7.392 11.329 7.416 ;
     RECT  11.045 2.736 11.333 2.76 ;
     RECT  11.329 7.392 11.365 7.464 ;
     RECT  10.45 10.32 11.365 10.584 ;
     RECT  11.189 13.344 11.365 14.664 ;
     RECT  11.185 9.12 11.369 9.144 ;
     RECT  11.149 18.192 11.441 19.368 ;
     RECT  10.835 28.8 11.509 28.824 ;
     RECT  10.433 29.808 11.509 34.152 ;
     RECT  11.441 18.192 11.513 18.792 ;
     RECT  11.189 24.336 11.513 25.944 ;
     RECT  11.365 10.128 11.581 10.584 ;
     RECT  11.189 11.904 11.581 12.312 ;
     RECT  11.509 28.8 11.585 34.152 ;
     RECT  11.149 16.128 11.833 16.152 ;
     RECT  11.689 17.232 11.833 17.256 ;
     RECT  11.581 10.128 11.869 12.312 ;
     RECT  11.005 36.048 11.869 40.68 ;
     RECT  10.924 21.696 11.905 23.064 ;
     RECT  11.869 35.712 11.941 40.68 ;
     RECT  11.365 7.104 11.977 7.752 ;
     RECT  11.905 21.264 12.049 23.064 ;
     RECT  11.513 24.336 12.049 24.36 ;
     RECT  11.941 28.464 12.049 28.488 ;
     RECT  11.585 29.52 12.085 34.152 ;
     RECT  11.941 35.184 12.085 40.68 ;
     RECT  11.581 26.928 12.157 26.952 ;
     RECT  12.049 28.272 12.157 28.488 ;
     RECT  11.297 3.888 12.265 5.304 ;
     RECT  11.977 7.104 12.445 8.28 ;
     RECT  11.513 18.432 12.517 18.792 ;
     RECT  12.157 19.92 12.517 19.944 ;
     RECT  11.869 9.792 12.769 12.312 ;
     RECT  12.265 3.024 12.812 5.304 ;
     RECT  12.445 7.104 12.812 8.712 ;
     RECT  12.769 9.792 12.913 12.36 ;
     RECT  11.365 13.344 12.913 15.048 ;
     RECT  11.513 25.392 12.985 25.944 ;
     RECT  12.157 26.928 12.985 28.488 ;
     RECT  12.913 9.792 13.021 15.048 ;
     RECT  11.833 16.128 13.021 17.256 ;
     RECT  12.812 3.024 13.093 8.712 ;
     RECT  13.021 9.792 13.093 17.256 ;
     RECT  12.049 21.264 13.093 24.36 ;
     RECT  12.985 25.392 13.093 28.488 ;
     RECT  12.085 29.52 13.129 40.68 ;
     RECT  13.129 29.52 13.165 40.872 ;
     RECT  13.093 3.024 13.208 17.256 ;
     RECT  12.517 18.432 13.208 19.944 ;
     RECT  13.093 21.264 13.208 28.488 ;
     RECT  13.165 29.52 13.208 40.968 ;
     RECT  13.208 2.148 13.312 41.052 ;
     RECT  13.312 2.208 13.504 40.968 ;
     RECT  13.504 2.208 13.565 3.048 ;
     RECT  13.504 15.744 13.565 22.872 ;
     RECT  13.504 4.128 13.889 14.232 ;
     RECT  13.504 39.792 13.889 40.968 ;
     RECT  13.889 9.792 14.069 14.232 ;
     RECT  13.504 27.36 14.213 28.68 ;
     RECT  13.889 39.888 14.213 40.968 ;
     RECT  14.213 39.888 14.285 40.872 ;
     RECT  13.889 4.128 14.291 8.568 ;
     RECT  14.069 9.84 14.537 14.232 ;
     RECT  13.565 2.208 14.573 2.568 ;
     RECT  13.565 15.744 14.573 22.728 ;
     RECT  14.213 27.888 14.605 28.68 ;
     RECT  13.504 30.336 14.605 38.808 ;
     RECT  14.291 4.416 14.675 8.568 ;
     RECT  14.573 21.168 14.771 22.728 ;
     RECT  14.537 11.28 14.869 14.232 ;
     RECT  13.504 24.336 14.893 26.376 ;
     RECT  14.573 15.744 14.897 20.184 ;
     RECT  14.285 40.128 14.897 40.872 ;
     RECT  14.897 15.744 14.933 19.032 ;
     RECT  14.605 27.888 14.933 38.808 ;
     RECT  14.537 9.84 15.005 9.96 ;
     RECT  15.005 9.936 15.041 9.96 ;
     RECT  14.869 11.28 15.073 14.568 ;
     RECT  14.933 15.744 15.073 18.84 ;
     RECT  14.893 23.904 15.073 26.376 ;
     RECT  14.675 8.016 15.113 8.568 ;
     RECT  15.113 8.112 15.155 8.568 ;
     RECT  15.073 23.664 15.157 26.376 ;
     RECT  15.155 8.208 15.193 8.568 ;
     RECT  15.157 23.664 15.244 26.664 ;
     RECT  15.193 8.256 15.329 8.568 ;
     RECT  15.329 8.448 15.349 8.568 ;
     RECT  15.244 23.664 15.401 26.28 ;
     RECT  15.401 23.664 15.436 25.896 ;
     RECT  14.933 30.336 15.469 38.808 ;
     RECT  14.897 40.128 15.469 40.824 ;
     RECT  14.771 21.168 15.473 22.536 ;
     RECT  15.073 11.28 15.505 18.84 ;
     RECT  14.933 27.888 15.509 29.064 ;
     RECT  15.505 10.656 15.653 18.84 ;
     RECT  14.897 20.16 15.653 20.184 ;
     RECT  14.573 2.208 15.685 2.232 ;
     RECT  14.821 3.408 15.685 3.432 ;
     RECT  15.685 2.208 15.725 3.432 ;
     RECT  15.653 13.2 15.725 18.84 ;
     RECT  15.473 21.168 15.793 21.912 ;
     RECT  15.725 16.512 15.833 18.84 ;
     RECT  15.725 2.496 15.875 3.432 ;
     RECT  15.793 20.304 15.877 21.912 ;
     RECT  15.833 18.432 15.941 18.84 ;
     RECT  15.653 10.656 16.085 12.024 ;
     RECT  15.509 27.888 16.121 29.016 ;
     RECT  15.349 8.448 16.229 8.904 ;
     RECT  15.469 30.336 16.297 40.824 ;
     RECT  15.436 23.664 16.301 25.8 ;
     RECT  15.877 21.648 16.445 21.912 ;
     RECT  16.297 30.336 16.477 40.872 ;
     RECT  15.833 16.512 16.481 17.352 ;
     RECT  16.477 30.288 16.549 40.872 ;
     RECT  16.085 10.656 16.589 11.976 ;
     RECT  16.229 8.592 16.697 8.904 ;
     RECT  16.589 11.184 16.697 11.976 ;
     RECT  14.675 4.416 16.733 6.984 ;
     RECT  16.301 24.336 16.765 25.8 ;
     RECT  16.549 30.048 16.805 40.872 ;
     RECT  16.697 8.88 16.981 8.904 ;
     RECT  16.445 21.888 17.021 21.912 ;
     RECT  16.765 24.336 17.021 26.52 ;
     RECT  15.875 2.496 17.057 2.76 ;
     RECT  17.021 24.768 17.057 26.52 ;
     RECT  16.481 16.992 17.093 17.352 ;
     RECT  16.697 11.184 17.165 11.784 ;
     RECT  15.725 13.2 17.165 15.384 ;
     RECT  17.093 17.088 17.201 17.352 ;
     RECT  15.941 18.432 17.269 18.6 ;
     RECT  15.877 20.304 17.273 20.328 ;
     RECT  16.805 30.048 17.345 40.824 ;
     RECT  16.981 8.88 17.372 9.288 ;
     RECT  16.121 27.984 17.449 29.016 ;
     RECT  17.345 30.048 17.449 40.632 ;
     RECT  17.372 8.88 17.459 9.768 ;
     RECT  17.459 8.88 17.489 9.288 ;
     RECT  17.269 18.432 17.525 19.272 ;
     RECT  17.525 18.72 17.701 19.272 ;
     RECT  17.413 23.328 17.737 23.352 ;
     RECT  17.165 13.2 17.773 15.096 ;
     RECT  17.057 2.736 17.809 2.76 ;
     RECT  17.165 11.664 17.845 11.784 ;
     RECT  17.809 2.736 18.025 3.288 ;
     RECT  18.025 2.736 18.092 3.432 ;
     RECT  18.092 2.256 18.133 3.432 ;
     RECT  16.733 5.088 18.133 6.984 ;
     RECT  17.057 24.768 18.169 25.8 ;
     RECT  17.773 13.056 18.205 15.096 ;
     RECT  17.201 17.328 18.241 17.352 ;
     RECT  18.133 2.256 18.277 6.984 ;
     RECT  17.449 27.984 18.349 40.632 ;
     RECT  18.205 13.056 18.469 15.72 ;
     RECT  18.241 17.088 18.469 17.352 ;
     RECT  17.737 23.328 18.469 23.544 ;
     RECT  18.169 24.528 18.469 25.8 ;
     RECT  18.277 2.256 18.608 7.224 ;
     RECT  17.489 9.12 18.608 9.288 ;
     RECT  17.845 11.664 18.608 12.024 ;
     RECT  18.469 13.056 18.608 17.352 ;
     RECT  17.701 18.72 18.608 19.368 ;
     RECT  17.701 20.544 18.608 20.568 ;
     RECT  18.469 22.8 18.608 26.04 ;
     RECT  18.349 27.6 18.608 40.632 ;
     RECT  18.608 2.148 18.712 41.052 ;
     RECT  18.712 2.418 18.904 40.824 ;
     RECT  18.904 3.408 18.929 7.944 ;
     RECT  18.904 9.264 19.001 10.2 ;
     RECT  18.904 19.344 19.001 20.424 ;
     RECT  18.904 15.984 19.109 18.168 ;
     RECT  18.929 3.936 19.397 7.944 ;
     RECT  19.109 17.04 19.397 18.168 ;
     RECT  19.001 19.344 19.427 19.944 ;
     RECT  19.001 10.128 19.613 10.2 ;
     RECT  19.613 10.128 19.685 10.152 ;
     RECT  19.397 3.936 19.829 5.592 ;
     RECT  19.829 5.568 19.865 5.592 ;
     RECT  19.829 3.936 19.897 4.44 ;
     RECT  19.897 3.408 19.964 4.44 ;
     RECT  19.964 3.024 20.005 4.44 ;
     RECT  18.904 11.664 20.005 14.808 ;
     RECT  18.904 25.056 20.005 26.04 ;
     RECT  20.005 2.256 20.051 4.44 ;
     RECT  20.005 24.912 20.069 26.04 ;
     RECT  18.904 27.456 20.069 40.824 ;
     RECT  20.069 24.912 20.081 40.824 ;
     RECT  18.904 22.176 20.113 23.928 ;
     RECT  20.081 24.912 20.113 27.48 ;
     RECT  19.397 6.672 20.221 7.944 ;
     RECT  19.397 17.04 20.441 17.4 ;
     RECT  19.427 19.92 20.441 19.944 ;
     RECT  20.221 6.672 20.473 8.52 ;
     RECT  19.109 15.984 20.473 16.008 ;
     RECT  20.441 17.04 20.473 17.352 ;
     RECT  20.005 11.664 20.485 14.952 ;
     RECT  20.473 15.984 20.485 17.352 ;
     RECT  20.113 22.176 20.549 27.48 ;
     RECT  20.473 6.672 20.689 9 ;
     RECT  20.689 6.624 20.761 9 ;
     RECT  20.485 11.664 20.761 17.352 ;
     RECT  19.969 20.928 20.761 20.952 ;
     RECT  20.549 22.176 20.761 26.808 ;
     RECT  20.761 6.528 20.819 9 ;
     RECT  20.819 6.528 20.869 7.176 ;
     RECT  20.761 19.968 20.905 20.952 ;
     RECT  20.761 22.128 20.905 26.808 ;
     RECT  20.761 11.472 20.941 17.352 ;
     RECT  20.941 11.136 20.945 17.352 ;
     RECT  20.819 8.496 20.981 9 ;
     RECT  20.869 6.336 21.049 7.176 ;
     RECT  20.945 11.136 21.049 15.432 ;
     RECT  20.051 3.456 21.085 4.44 ;
     RECT  21.049 5.856 21.085 7.176 ;
     RECT  20.081 28.512 21.125 40.824 ;
     RECT  21.049 10.704 21.373 15.432 ;
     RECT  21.373 10.368 21.395 15.432 ;
     RECT  20.761 18.48 21.395 18.504 ;
     RECT  20.945 17.136 21.445 17.352 ;
     RECT  21.125 30.624 21.449 40.824 ;
     RECT  20.051 2.256 21.548 2.28 ;
     RECT  21.085 3.456 21.548 7.176 ;
     RECT  20.905 19.968 21.589 26.808 ;
     RECT  21.445 17.136 21.625 17.448 ;
     RECT  21.548 2.256 21.635 7.176 ;
     RECT  21.635 2.256 21.773 2.28 ;
     RECT  20.981 8.592 21.809 9 ;
     RECT  21.589 19.296 21.949 27.096 ;
     RECT  21.125 28.512 22.093 29.112 ;
     RECT  21.625 17.136 22.129 17.496 ;
     RECT  21.395 13.584 22.385 15.432 ;
     RECT  21.949 19.296 22.417 27.528 ;
     RECT  22.093 28.512 22.417 29.256 ;
     RECT  22.417 19.296 22.489 29.256 ;
     RECT  22.129 16.512 22.561 17.496 ;
     RECT  21.635 3.456 22.669 7.176 ;
     RECT  22.561 16.224 22.741 17.496 ;
     RECT  21.809 8.592 22.777 8.616 ;
     RECT  21.395 10.368 22.813 12.552 ;
     RECT  22.385 13.584 22.813 13.656 ;
     RECT  22.741 16.224 22.828 17.832 ;
     RECT  22.489 19.008 22.889 29.256 ;
     RECT  22.777 8.496 22.957 8.76 ;
     RECT  22.957 8.496 22.993 8.856 ;
     RECT  22.813 10.368 22.997 13.656 ;
     RECT  22.669 3.456 23.065 7.368 ;
     RECT  22.993 8.4 23.065 8.856 ;
     RECT  22.997 10.368 23.065 13.56 ;
     RECT  21.449 30.816 23.245 40.824 ;
     RECT  23.065 3.312 23.353 7.368 ;
     RECT  23.065 8.4 23.353 13.56 ;
     RECT  22.889 19.008 23.713 28.968 ;
     RECT  22.385 14.64 23.893 14.664 ;
     RECT  22.828 16.224 23.893 17.4 ;
     RECT  23.353 3.312 24.008 13.56 ;
     RECT  23.893 14.64 24.008 17.4 ;
     RECT  23.713 18.816 24.008 28.968 ;
     RECT  23.245 30.816 24.008 41.016 ;
     RECT  24.008 2.148 24.112 41.052 ;
     RECT  24.112 2.256 24.304 40.782 ;
     RECT  24.304 2.256 24.329 5.208 ;
     RECT  24.304 18.48 24.365 19.272 ;
     RECT  24.329 2.256 24.401 3.048 ;
     RECT  24.304 6.288 24.473 10.392 ;
     RECT  24.473 6.288 24.508 9.96 ;
     RECT  24.365 18.72 24.509 19.272 ;
     RECT  24.304 21.744 24.653 25.8 ;
     RECT  24.304 17.232 24.725 17.496 ;
     RECT  24.653 21.744 25.013 25.752 ;
     RECT  24.329 4.128 25.085 5.208 ;
     RECT  24.725 17.28 25.085 17.496 ;
     RECT  24.508 6.432 25.229 9.96 ;
     RECT  24.304 11.52 25.297 12.888 ;
     RECT  24.304 14.208 25.337 15.288 ;
     RECT  24.304 20.688 25.373 20.712 ;
     RECT  25.013 22.512 25.373 25.752 ;
     RECT  25.297 11.52 25.409 13.08 ;
     RECT  24.509 18.768 25.553 19.272 ;
     RECT  25.409 11.52 25.621 11.976 ;
     RECT  24.304 27.072 25.625 40.44 ;
     RECT  25.085 4.128 25.657 4.152 ;
     RECT  25.337 14.64 25.661 15.288 ;
     RECT  25.657 3.792 25.685 4.152 ;
     RECT  25.373 24.96 25.805 25.752 ;
     RECT  24.401 2.256 25.913 2.28 ;
     RECT  25.625 39.6 25.949 40.44 ;
     RECT  25.373 22.512 26.053 23.976 ;
     RECT  26.053 22.416 26.093 23.976 ;
     RECT  25.229 6.432 26.125 9.672 ;
     RECT  25.625 27.072 26.125 38.424 ;
     RECT  26.093 22.416 26.197 23.112 ;
     RECT  25.661 14.64 26.243 14.904 ;
     RECT  26.125 26.88 26.269 38.424 ;
     RECT  25.621 11.136 26.273 11.976 ;
     RECT  25.729 19.392 26.348 19.464 ;
     RECT  25.585 20.736 26.348 20.76 ;
     RECT  25.409 13.056 26.377 13.08 ;
     RECT  26.377 13.056 26.417 13.656 ;
     RECT  26.348 19.392 26.417 20.76 ;
     RECT  26.125 6.336 26.424 9.672 ;
     RECT  26.417 19.392 26.435 20.04 ;
     RECT  26.424 6.24 26.483 9.672 ;
     RECT  26.197 2.304 26.485 2.328 ;
     RECT  25.685 3.408 26.485 4.152 ;
     RECT  26.435 19.392 26.531 19.464 ;
     RECT  26.243 14.88 26.589 14.904 ;
     RECT  25.805 25.056 26.773 25.752 ;
     RECT  26.269 26.736 26.773 38.424 ;
     RECT  26.485 2.304 26.809 4.152 ;
     RECT  25.085 5.184 26.809 5.208 ;
     RECT  26.273 11.136 26.813 11.4 ;
     RECT  26.809 2.304 26.849 5.208 ;
     RECT  26.773 25.056 26.915 38.424 ;
     RECT  26.915 25.056 26.917 26.904 ;
     RECT  26.197 22.032 26.957 23.112 ;
     RECT  26.849 3.792 27.061 5.208 ;
     RECT  26.483 6.24 27.061 8.856 ;
     RECT  26.485 16.032 27.061 16.056 ;
     RECT  25.801 18.144 27.065 18.168 ;
     RECT  26.917 24.672 27.173 26.904 ;
     RECT  27.061 15.312 27.277 16.056 ;
     RECT  25.873 17.04 27.277 17.064 ;
     RECT  25.949 40.032 27.349 40.44 ;
     RECT  27.277 15.312 27.389 17.064 ;
     RECT  26.531 19.44 27.389 19.464 ;
     RECT  26.957 22.032 27.389 22.536 ;
     RECT  27.061 3.792 27.425 8.856 ;
     RECT  26.813 11.376 27.529 11.4 ;
     RECT  26.849 2.304 27.587 2.808 ;
     RECT  27.425 6.096 27.605 8.856 ;
     RECT  27.605 6.096 27.635 7.08 ;
     RECT  27.605 8.064 27.637 8.856 ;
     RECT  27.635 6.096 27.749 6.984 ;
     RECT  26.417 13.344 27.781 13.656 ;
     RECT  27.637 20.304 27.889 20.328 ;
     RECT  27.709 21.408 27.889 21.432 ;
     RECT  26.915 27.888 27.889 38.424 ;
     RECT  27.637 8.064 27.893 9.096 ;
     RECT  27.893 8.832 27.965 9.096 ;
     RECT  27.173 24.672 28.001 26.232 ;
     RECT  27.389 15.312 28.033 17.016 ;
     RECT  28.001 24.672 28.037 24.696 ;
     RECT  27.889 27.456 28.141 38.424 ;
     RECT  28.141 27.408 28.213 38.424 ;
     RECT  28.001 25.728 28.249 26.232 ;
     RECT  28.213 27.36 28.249 38.424 ;
     RECT  28.033 14.88 28.393 17.016 ;
     RECT  27.389 22.512 28.465 22.536 ;
     RECT  27.781 13.296 28.501 13.656 ;
     RECT  28.393 14.88 28.501 17.16 ;
     RECT  27.529 11.376 28.537 12.216 ;
     RECT  28.501 13.296 28.537 17.16 ;
     RECT  28.249 25.728 28.573 38.424 ;
     RECT  28.537 11.376 28.645 17.16 ;
     RECT  28.645 10.608 28.681 17.16 ;
     RECT  27.425 3.792 28.753 4.872 ;
     RECT  27.889 20.304 28.789 21.432 ;
     RECT  28.465 22.512 28.789 23.304 ;
     RECT  27.965 8.832 28.969 8.856 ;
     RECT  28.969 8.832 29.005 9.144 ;
     RECT  28.573 25.728 29.257 39.048 ;
     RECT  27.349 40.032 29.257 40.68 ;
     RECT  27.587 2.304 29.365 2.328 ;
     RECT  28.753 3.792 29.365 5.064 ;
     RECT  27.749 6.144 29.365 6.984 ;
     RECT  29.365 2.304 29.408 2.808 ;
     RECT  29.365 3.792 29.408 6.984 ;
     RECT  29.005 8.736 29.408 9.144 ;
     RECT  28.681 10.608 29.408 17.64 ;
     RECT  28.789 20.304 29.408 23.304 ;
     RECT  29.401 24.48 29.408 24.504 ;
     RECT  29.257 25.728 29.408 40.68 ;
     RECT  29.408 2.148 29.512 41.052 ;
     RECT  29.512 2.418 29.704 40.782 ;
     RECT  29.704 26.112 29.729 39.816 ;
     RECT  29.704 3.936 29.801 7.32 ;
     RECT  29.801 3.936 30.125 5.592 ;
     RECT  29.704 10.32 30.449 12.552 ;
     RECT  29.729 29.616 30.521 39.816 ;
     RECT  30.125 4.464 30.665 5.592 ;
     RECT  29.704 2.544 30.737 2.808 ;
     RECT  29.801 6.672 30.805 7.32 ;
     RECT  29.704 13.872 30.841 24.6 ;
     RECT  30.449 10.32 30.845 12.312 ;
     RECT  30.665 4.464 30.989 4.968 ;
     RECT  30.841 13.536 30.989 24.6 ;
     RECT  30.805 6.096 31.169 7.944 ;
     RECT  30.989 13.872 31.235 24.6 ;
     RECT  30.989 4.464 31.237 4.728 ;
     RECT  30.521 32.256 31.309 39.816 ;
     RECT  31.235 14.16 31.561 24.6 ;
     RECT  29.729 26.112 31.561 28.584 ;
     RECT  30.521 29.616 31.561 30.936 ;
     RECT  31.309 32.256 31.633 40.152 ;
     RECT  31.733 9.12 31.817 9.144 ;
     RECT  30.737 2.784 31.849 2.808 ;
     RECT  31.169 6.24 31.852 7.944 ;
     RECT  31.561 14.16 32.033 30.936 ;
     RECT  31.633 32.112 32.065 40.152 ;
     RECT  32.033 19.632 32.101 30.936 ;
     RECT  32.065 32.112 32.101 40.44 ;
     RECT  31.849 2.784 32.173 2.904 ;
     RECT  31.237 4.224 32.245 4.728 ;
     RECT  32.173 2.496 32.425 2.904 ;
     RECT  32.245 3.984 32.425 5.016 ;
     RECT  30.845 10.32 32.461 12.024 ;
     RECT  31.852 6.24 32.501 7.272 ;
     RECT  32.425 2.496 32.965 5.016 ;
     RECT  32.501 6.288 32.965 7.272 ;
     RECT  32.461 10.32 33.001 12.072 ;
     RECT  32.965 2.496 33.013 5.112 ;
     RECT  33.013 2.256 33.059 5.112 ;
     RECT  32.033 14.16 33.061 18.6 ;
     RECT  32.101 19.632 33.061 40.44 ;
     RECT  33.059 2.256 33.077 2.52 ;
     RECT  33.001 10.32 33.205 12.36 ;
     RECT  33.205 10.176 33.292 12.36 ;
     RECT  33.059 3.6 33.577 5.112 ;
     RECT  32.965 6.288 33.577 7.416 ;
     RECT  33.077 2.256 33.581 2.28 ;
     RECT  33.061 14.16 33.683 40.44 ;
     RECT  33.577 3.6 33.937 7.416 ;
     RECT  33.937 3.6 34.153 7.992 ;
     RECT  33.683 14.16 34.225 40.152 ;
     RECT  33.292 10.32 34.261 12.36 ;
     RECT  34.261 10.32 34.369 12.456 ;
     RECT  34.369 10.128 34.405 12.456 ;
     RECT  34.225 13.68 34.405 40.152 ;
     RECT  34.153 3.408 34.808 7.992 ;
     RECT  32.281 9.072 34.808 9.096 ;
     RECT  34.405 10.128 34.808 40.152 ;
     RECT  34.808 2.148 34.912 41.052 ;
     RECT  34.912 2.418 35.104 40.782 ;
     RECT  35.104 9.024 35.165 26.664 ;
     RECT  35.104 31.152 35.165 40.152 ;
     RECT  35.165 31.152 35.273 39.576 ;
     RECT  35.273 31.44 35.381 39.576 ;
     RECT  35.165 9.024 35.777 26.088 ;
     RECT  35.104 2.88 35.957 7.992 ;
     RECT  35.957 4.8 35.993 7.992 ;
     RECT  35.777 9.024 36.028 22.728 ;
     RECT  35.993 4.8 36.035 7.464 ;
     RECT  35.381 37.104 36.169 39.576 ;
     RECT  35.104 27.648 36.277 30.168 ;
     RECT  36.035 5.088 36.323 7.464 ;
     RECT  36.277 27.648 36.529 30.456 ;
     RECT  35.381 31.44 36.529 35.832 ;
     RECT  36.529 27.648 36.781 35.832 ;
     RECT  36.781 27.648 36.853 35.88 ;
     RECT  36.169 37.104 36.853 40.488 ;
     RECT  36.853 27.648 36.857 40.488 ;
     RECT  35.957 2.88 36.86 3.336 ;
     RECT  36.86 2.256 36.947 3.336 ;
     RECT  35.777 23.712 37.045 26.088 ;
     RECT  36.857 27.648 37.045 37.272 ;
     RECT  36.028 9.072 37.069 22.728 ;
     RECT  37.045 23.712 37.145 37.272 ;
     RECT  37.145 27.984 37.217 37.272 ;
     RECT  36.323 6.576 37.253 7.464 ;
     RECT  37.253 6.864 37.321 7.464 ;
     RECT  36.323 5.088 37.357 5.112 ;
     RECT  37.321 6.864 37.429 7.752 ;
     RECT  37.069 8.784 37.429 22.728 ;
     RECT  36.947 2.88 37.501 3.336 ;
     RECT  37.429 6.864 37.537 22.728 ;
     RECT  37.145 23.712 37.537 26.808 ;
     RECT  37.501 2.88 37.717 4.104 ;
     RECT  37.357 5.088 37.717 5.736 ;
     RECT  37.717 2.88 37.757 5.736 ;
     RECT  37.757 2.88 37.901 4.536 ;
     RECT  36.857 38.688 37.901 40.488 ;
     RECT  37.537 6.864 38.225 26.808 ;
     RECT  38.149 37.584 38.257 37.608 ;
     RECT  37.901 38.688 38.257 40.344 ;
     RECT  37.217 27.984 38.437 36.6 ;
     RECT  38.257 37.584 38.437 40.344 ;
     RECT  38.225 7.392 38.545 26.808 ;
     RECT  38.437 27.984 38.837 40.344 ;
     RECT  37.757 5.52 38.869 5.736 ;
     RECT  38.837 27.984 38.873 37.992 ;
     RECT  37.901 3.312 38.945 4.536 ;
     RECT  38.545 7.392 39.229 26.904 ;
     RECT  38.873 27.984 39.229 28.728 ;
     RECT  39.193 1.728 39.277 1.752 ;
     RECT  38.869 5.52 39.337 6.264 ;
     RECT  39.229 7.392 39.337 28.728 ;
     RECT  38.945 3.312 39.553 3.336 ;
     RECT  38.837 39.072 39.685 40.344 ;
     RECT  39.685 39.072 39.869 40.872 ;
     RECT  38.945 4.512 39.877 4.536 ;
     RECT  39.337 5.52 39.877 28.728 ;
     RECT  39.493 43.008 39.973 43.128 ;
     RECT  39.877 4.512 40.057 28.728 ;
     RECT  38.873 29.76 40.057 37.992 ;
     RECT  39.553 2.832 40.065 3.336 ;
     RECT  39.973 42.144 40.133 43.128 ;
     RECT  40.057 4.512 40.165 37.992 ;
     RECT  39.869 39.072 40.165 41.016 ;
     RECT  40.133 42.912 40.201 43.128 ;
     RECT  40.065 2.832 40.208 3.432 ;
     RECT  40.165 4.512 40.208 41.208 ;
     RECT  40.208 2.148 40.307 41.208 ;
     RECT  40.307 2.148 40.312 41.16 ;
     RECT  40.312 2.256 40.504 41.16 ;
     RECT  40.504 7.344 40.637 26.664 ;
     RECT  40.201 42.912 40.637 43.176 ;
     RECT  40.504 27.888 40.709 41.16 ;
     RECT  40.709 28.512 40.925 41.16 ;
     RECT  40.925 28.512 41.177 41.016 ;
     RECT  40.504 2.256 41.315 3.768 ;
     RECT  40.637 7.344 41.501 26.568 ;
     RECT  41.177 28.752 41.501 41.016 ;
     RECT  41.315 2.496 41.573 3.768 ;
     RECT  41.501 28.896 41.645 41.016 ;
     RECT  41.573 2.88 41.677 3.768 ;
     RECT  40.504 4.896 41.677 5.592 ;
     RECT  41.645 28.896 41.825 40.872 ;
     RECT  41.605 27.264 41.929 27.288 ;
     RECT  41.501 7.344 41.933 26.136 ;
     RECT  41.677 2.88 42.109 5.592 ;
     RECT  41.933 7.344 42.109 26.088 ;
     RECT  41.929 27.264 42.361 27.384 ;
     RECT  42.361 27.264 42.469 27.912 ;
     RECT  40.637 43.056 42.473 43.176 ;
     RECT  41.825 28.944 42.905 40.872 ;
     RECT  42.905 31.872 42.937 40.872 ;
     RECT  42.905 28.944 42.941 30.84 ;
     RECT  42.937 31.872 43.121 40.92 ;
     RECT  42.473 43.104 43.157 43.176 ;
     RECT  43.121 31.872 43.229 40.872 ;
     RECT  42.109 2.88 43.297 26.088 ;
     RECT  43.297 2.304 43.301 26.088 ;
     RECT  42.469 27.216 43.58 27.912 ;
     RECT  42.941 28.944 43.58 30.696 ;
     RECT  43.229 40.608 43.589 40.872 ;
     RECT  43.301 7.68 43.621 26.088 ;
     RECT  43.58 27.216 43.621 30.696 ;
     RECT  43.229 31.872 43.697 39.336 ;
     RECT  43.697 31.872 43.949 34.44 ;
     RECT  43.301 2.304 44.147 6.648 ;
     RECT  44.147 2.304 44.165 3.912 ;
     RECT  43.697 35.472 44.269 39.336 ;
     RECT  43.157 43.152 44.309 43.176 ;
     RECT  44.147 5.184 44.524 6.648 ;
     RECT  44.524 5.472 44.677 6.648 ;
     RECT  43.621 7.68 44.677 30.696 ;
     RECT  44.165 3.312 45.308 3.912 ;
     RECT  44.677 5.472 45.493 30.696 ;
     RECT  43.949 31.968 45.493 34.44 ;
     RECT  45.308 3.312 45.601 4.392 ;
     RECT  45.493 5.472 45.601 34.44 ;
     RECT  44.165 2.304 45.608 2.328 ;
     RECT  45.601 3.312 45.608 34.44 ;
     RECT  44.269 35.472 45.608 39.384 ;
     RECT  43.589 40.848 45.608 40.872 ;
     RECT  45.608 2.148 45.712 41.052 ;
     RECT  45.712 2.304 45.904 40.968 ;
     RECT  45.904 38.208 46.181 40.968 ;
     RECT  46.181 38.208 46.217 39.624 ;
     RECT  45.904 30.048 46.325 30.696 ;
     RECT  46.325 30.048 46.793 30.6 ;
     RECT  45.904 31.776 46.793 36.936 ;
     RECT  45.904 2.304 46.829 27.912 ;
     RECT  46.793 34.992 47.077 36.936 ;
     RECT  46.829 3.072 47.225 27.912 ;
     RECT  46.793 30.576 47.405 30.6 ;
     RECT  46.217 38.736 47.405 39.624 ;
     RECT  46.181 40.704 47.437 40.968 ;
     RECT  47.077 34.992 47.441 37.032 ;
     RECT  47.405 38.928 47.473 39.624 ;
     RECT  47.437 40.656 47.473 40.968 ;
     RECT  47.225 26.592 47.519 27.912 ;
     RECT  47.225 3.072 47.548 25.56 ;
     RECT  47.473 38.928 47.693 40.968 ;
     RECT  47.441 35.424 47.797 37.032 ;
     RECT  47.797 35.424 47.833 37.656 ;
     RECT  47.833 35.424 47.837 37.752 ;
     RECT  46.793 31.776 47.977 34.008 ;
     RECT  47.548 3.072 48.121 6.36 ;
     RECT  48.121 2.256 48.227 6.36 ;
     RECT  47.548 7.344 48.323 25.56 ;
     RECT  47.837 35.472 48.341 37.752 ;
     RECT  47.519 26.592 48.409 28.44 ;
     RECT  46.969 29.472 48.409 29.496 ;
     RECT  47.977 31.104 48.521 34.008 ;
     RECT  48.409 26.592 48.524 29.496 ;
     RECT  48.521 31.104 48.773 33.72 ;
     RECT  47.693 39.888 48.773 40.968 ;
     RECT  48.227 3.072 48.881 6.36 ;
     RECT  48.524 26.544 48.989 29.496 ;
     RECT  48.341 37.536 49.061 37.752 ;
     RECT  48.773 33.6 49.097 33.72 ;
     RECT  48.881 3.072 49.169 6.072 ;
     RECT  49.097 33.648 49.205 33.72 ;
     RECT  48.341 35.472 49.381 36.36 ;
     RECT  49.381 35.328 49.421 36.36 ;
     RECT  48.773 31.104 49.493 32.472 ;
     RECT  48.323 7.488 49.525 25.56 ;
     RECT  48.989 26.544 49.525 29.352 ;
     RECT  49.061 37.536 49.601 37.608 ;
     RECT  48.773 40.32 49.637 40.968 ;
     RECT  49.205 33.648 49.781 33.672 ;
     RECT  49.525 7.488 50.029 29.352 ;
     RECT  50.029 7.488 50.101 29.64 ;
     RECT  49.169 3.072 50.137 5.64 ;
     RECT  49.601 37.584 50.137 37.608 ;
     RECT  49.345 38.64 50.137 38.664 ;
     RECT  50.137 3.072 50.173 6.36 ;
     RECT  50.173 3.024 50.209 6.36 ;
     RECT  50.209 2.352 50.341 6.36 ;
     RECT  50.101 7.488 50.341 29.928 ;
     RECT  50.137 37.584 50.461 38.664 ;
     RECT  50.461 37.584 50.485 39.336 ;
     RECT  49.637 40.32 50.485 40.488 ;
     RECT  49.421 35.328 50.813 36.216 ;
     RECT  50.341 2.352 50.849 29.928 ;
     RECT  49.493 31.104 50.849 31.8 ;
     RECT  50.849 2.352 51.008 31.8 ;
     RECT  50.173 33.6 51.008 33.624 ;
     RECT  50.813 34.8 51.008 36.216 ;
     RECT  50.485 37.584 51.008 40.488 ;
     RECT  51.008 2.148 51.112 41.052 ;
     RECT  51.112 2.352 51.304 40.782 ;
     RECT  51.304 2.352 51.365 25.464 ;
     RECT  51.304 26.784 51.365 30.072 ;
     RECT  51.365 6.576 51.401 25.464 ;
     RECT  51.304 37.872 51.833 38.232 ;
     RECT  51.304 31.248 51.905 32.52 ;
     RECT  51.304 34.752 52.019 36.744 ;
     RECT  51.905 31.248 52.067 32.472 ;
     RECT  51.365 2.352 52.193 5.592 ;
     RECT  51.365 27.12 52.333 30.072 ;
     RECT  51.401 7.344 52.337 25.464 ;
     RECT  52.193 4.512 52.405 5.592 ;
     RECT  52.333 27.072 52.405 30.072 ;
     RECT  51.304 33.6 52.405 33.624 ;
     RECT  52.193 2.352 52.445 3.144 ;
     RECT  52.067 31.248 52.445 31.272 ;
     RECT  51.304 39.6 52.453 40.008 ;
     RECT  52.405 26.736 52.477 30.072 ;
     RECT  52.445 2.544 52.481 3.144 ;
     RECT  52.337 7.344 52.499 25.272 ;
     RECT  52.019 35.328 52.513 36.744 ;
     RECT  52.481 2.736 52.589 3.144 ;
     RECT  52.499 7.344 52.765 25.176 ;
     RECT  52.589 2.736 52.769 2.76 ;
     RECT  52.513 35.328 52.769 37.704 ;
     RECT  52.453 39.6 52.883 40.584 ;
     RECT  52.477 26.4 52.909 30.072 ;
     RECT  52.769 35.328 52.913 37.08 ;
     RECT  52.883 39.984 52.913 40.584 ;
     RECT  52.909 26.4 53.027 30.792 ;
     RECT  52.405 33.6 53.093 34.152 ;
     RECT  52.913 35.328 53.413 36.216 ;
     RECT  52.801 38.064 53.413 38.376 ;
     RECT  52.405 4.512 53.449 6.264 ;
     RECT  52.067 32.448 53.449 32.472 ;
     RECT  53.093 33.696 53.561 34.152 ;
     RECT  53.449 4.32 53.881 6.264 ;
     RECT  53.413 35.136 53.957 36.216 ;
     RECT  53.449 32.448 54.025 32.616 ;
     RECT  54.061 2.256 54.095 2.28 ;
     RECT  53.881 4.032 54.095 6.264 ;
     RECT  54.095 2.256 54.133 6.264 ;
     RECT  54.133 2.256 54.179 6.312 ;
     RECT  52.913 40.56 54.317 40.584 ;
     RECT  53.413 38.064 54.353 39 ;
     RECT  53.561 34.128 54.457 34.152 ;
     RECT  53.957 35.136 54.457 35.352 ;
     RECT  54.353 38.976 54.605 39 ;
     RECT  53.027 26.4 54.637 30.456 ;
     RECT  54.025 31.536 54.637 32.616 ;
     RECT  54.637 36.96 54.673 36.984 ;
     RECT  54.457 34.128 54.755 35.352 ;
     RECT  54.179 2.832 54.785 6.312 ;
     RECT  54.755 34.416 54.821 35.352 ;
     RECT  52.765 7.296 54.853 25.176 ;
     RECT  54.637 26.4 54.853 32.616 ;
     RECT  54.821 34.704 54.929 35.352 ;
     RECT  54.853 7.296 54.961 32.616 ;
     RECT  54.673 36.96 54.997 37.08 ;
     RECT  54.929 35.328 55.033 35.352 ;
     RECT  54.997 36.432 55.033 37.08 ;
     RECT  55.033 35.328 55.081 37.08 ;
     RECT  54.785 3.216 55.177 6.312 ;
     RECT  54.961 7.296 55.177 32.76 ;
     RECT  55.081 36.96 55.181 37.08 ;
     RECT  55.177 3.216 55.325 32.76 ;
     RECT  55.081 35.328 55.325 35.496 ;
     RECT  55.181 37.008 55.573 37.08 ;
     RECT  55.325 31.92 55.753 32.76 ;
     RECT  55.325 3.216 56.005 30.888 ;
     RECT  55.325 35.472 56.221 35.496 ;
     RECT  55.573 37.008 56.221 38.664 ;
     RECT  56.005 2.256 56.329 30.888 ;
     RECT  55.753 31.92 56.329 33.144 ;
     RECT  56.329 2.256 56.408 33.144 ;
     RECT  56.221 35.472 56.408 38.664 ;
     RECT  55.537 40.656 56.408 40.68 ;
     RECT  56.408 2.148 56.512 41.052 ;
     RECT  56.512 2.256 56.704 40.782 ;
     RECT  56.704 34.752 56.801 37.896 ;
     RECT  56.704 2.256 56.819 2.856 ;
     RECT  56.704 7.776 56.819 27.72 ;
     RECT  56.704 28.752 56.837 32.856 ;
     RECT  56.837 28.752 57.011 30.888 ;
     RECT  56.704 5.52 57.089 6.312 ;
     RECT  56.837 31.92 57.161 32.856 ;
     RECT  56.819 24.96 57.587 27.72 ;
     RECT  56.819 7.776 57.593 23.928 ;
     RECT  57.011 29.28 57.665 30.888 ;
     RECT  57.587 26.256 57.733 27.72 ;
     RECT  57.733 26.256 57.881 27.96 ;
     RECT  56.704 38.928 57.913 38.952 ;
     RECT  56.704 40.656 57.913 40.68 ;
     RECT  57.913 40.656 57.953 40.872 ;
     RECT  57.161 32.304 57.98 32.856 ;
     RECT  57.913 38.928 58.057 39.24 ;
     RECT  57.593 10.176 58.067 23.928 ;
     RECT  57.98 32.304 58.067 33.096 ;
     RECT  57.665 29.28 58.165 30.6 ;
     RECT  58.067 12.624 58.169 23.928 ;
     RECT  58.165 29.088 58.169 30.6 ;
     RECT  57.587 24.96 58.277 25.08 ;
     RECT  57.593 7.776 58.489 9.144 ;
     RECT  58.067 32.304 58.493 32.856 ;
     RECT  56.801 34.752 58.669 37.512 ;
     RECT  58.057 38.832 58.669 39.624 ;
     RECT  58.277 24.96 58.709 24.984 ;
     RECT  57.881 26.256 58.78 27.24 ;
     RECT  58.169 29.088 58.813 30.36 ;
     RECT  58.489 7.008 58.883 9.144 ;
     RECT  58.669 34.752 58.889 39.624 ;
     RECT  58.493 32.304 58.925 32.472 ;
     RECT  58.889 34.752 58.933 36.456 ;
     RECT  58.925 32.304 58.979 32.328 ;
     RECT  58.889 37.632 58.979 39.624 ;
     RECT  58.78 26.256 58.997 27.192 ;
     RECT  57.089 5.52 59.101 5.592 ;
     RECT  58.979 37.632 59.105 37.704 ;
     RECT  58.169 12.624 59.177 23.88 ;
     RECT  59.177 15.792 59.219 23.88 ;
     RECT  58.813 28.8 59.281 30.36 ;
     RECT  59.101 4.8 59.285 5.592 ;
     RECT  59.219 15.936 59.285 23.88 ;
     RECT  59.285 4.8 59.321 5.544 ;
     RECT  58.979 38.736 59.324 39.624 ;
     RECT  58.933 34.32 59.357 36.456 ;
     RECT  59.324 38.736 59.365 39.864 ;
     RECT  57.953 40.848 59.365 40.872 ;
     RECT  59.357 34.32 59.393 35.352 ;
     RECT  59.365 38.736 59.411 40.872 ;
     RECT  58.883 7.008 59.425 8.952 ;
     RECT  58.997 27.12 59.465 27.192 ;
     RECT  59.357 36.432 59.501 36.456 ;
     RECT  59.281 28.8 59.605 30.696 ;
     RECT  59.605 28.8 59.609 30.744 ;
     RECT  59.393 34.752 59.717 35.352 ;
     RECT  59.105 37.68 59.789 37.704 ;
     RECT  59.411 38.736 59.789 40.488 ;
     RECT  56.819 2.832 59.821 2.856 ;
     RECT  59.789 38.736 59.843 39.096 ;
     RECT  59.609 30.72 59.845 30.744 ;
     RECT  59.845 30.72 59.891 30.84 ;
     RECT  59.285 15.936 60.005 22.872 ;
     RECT  59.285 23.856 60.037 23.88 ;
     RECT  59.821 2.496 60.109 2.856 ;
     RECT  59.789 40.464 60.113 40.488 ;
     RECT  60.005 15.984 60.149 22.872 ;
     RECT  59.425 6.816 60.181 8.952 ;
     RECT  60.181 6.624 60.217 8.952 ;
     RECT  58.067 10.176 60.217 11.64 ;
     RECT  60.149 16.128 60.221 22.872 ;
     RECT  59.321 5.136 60.227 5.544 ;
     RECT  60.217 6.624 60.268 11.64 ;
     RECT  60.268 7.92 60.329 11.64 ;
     RECT  59.891 30.816 60.361 30.84 ;
     RECT  59.209 31.92 60.361 31.944 ;
     RECT  60.329 9.84 60.365 11.64 ;
     RECT  59.609 28.8 60.365 29.64 ;
     RECT  60.037 23.856 60.397 23.976 ;
     RECT  59.717 35.328 60.401 35.352 ;
     RECT  59.177 12.624 60.433 14.808 ;
     RECT  60.221 16.32 60.473 22.872 ;
     RECT  60.361 30.816 60.473 31.944 ;
     RECT  60.109 2.496 60.509 3.288 ;
     RECT  60.365 29.328 60.509 29.64 ;
     RECT  60.473 16.32 60.515 18.12 ;
     RECT  59.843 38.736 60.617 38.808 ;
     RECT  60.397 23.856 60.757 24.12 ;
     RECT  60.329 7.92 60.761 8.568 ;
     RECT  60.473 19.2 60.761 22.872 ;
     RECT  60.473 30.816 60.761 31.464 ;
     RECT  59.465 27.168 61.189 27.192 ;
     RECT  60.515 16.32 61.613 17.928 ;
     RECT  60.509 2.496 61.808 2.52 ;
     RECT  61.225 3.984 61.808 4.008 ;
     RECT  60.227 5.52 61.808 5.544 ;
     RECT  60.268 6.624 61.808 6.648 ;
     RECT  60.761 8.544 61.808 8.568 ;
     RECT  60.365 9.84 61.808 11.4 ;
     RECT  60.433 12.528 61.808 14.808 ;
     RECT  61.613 16.32 61.808 18.6 ;
     RECT  60.761 19.872 61.808 22.872 ;
     RECT  60.757 23.856 61.808 24.216 ;
     RECT  61.189 26.784 61.808 27.192 ;
     RECT  60.509 29.616 61.808 29.64 ;
     RECT  60.761 30.816 61.808 30.84 ;
     RECT  61.225 34.752 61.808 34.776 ;
     RECT  61.189 35.76 61.808 35.784 ;
     RECT  60.949 37.44 61.808 37.464 ;
     RECT  60.617 38.736 61.808 38.76 ;
     RECT  61.808 2.148 61.912 41.052 ;
     RECT  61.912 2.418 62.104 40.782 ;
     RECT  62.104 12.336 62.339 12.36 ;
     RECT  62.104 15.984 62.339 16.152 ;
     RECT  62.339 15.984 62.453 16.008 ;
     RECT  62.104 19.536 63.205 21.288 ;
     RECT  62.104 22.416 63.205 22.44 ;
     RECT  63.205 19.536 63.241 22.44 ;
     RECT  63.241 19.536 63.745 22.632 ;
     RECT  63.745 19.536 63.817 22.92 ;
     RECT  63.817 19.44 64.764 22.92 ;
    LAYER M5 ;
     RECT  39.12 0.016 39.24 1.763 ;
     RECT  2.4 2.137 2.52 2.151 ;
     RECT  7.8 2.137 7.92 2.151 ;
     RECT  13.2 2.137 13.32 2.151 ;
     RECT  18.6 2.137 18.72 2.151 ;
     RECT  24 2.137 24.12 2.151 ;
     RECT  29.4 2.137 29.52 2.151 ;
     RECT  34.8 2.137 34.92 2.151 ;
     RECT  40.2 2.137 40.32 2.151 ;
     RECT  45.6 2.137 45.72 2.151 ;
     RECT  51 2.137 51.12 2.151 ;
     RECT  56.4 2.137 56.52 2.151 ;
     RECT  61.8 2.137 61.92 2.151 ;
     RECT  18.6 2.151 18.912 2.245 ;
     RECT  40.2 2.151 40.512 2.245 ;
     RECT  56.4 2.151 56.712 2.245 ;
     RECT  51 2.151 51.312 2.341 ;
     RECT  61.8 2.151 62.112 2.485 ;
     RECT  25.728 2.245 25.752 2.821 ;
     RECT  56.4 2.245 56.808 2.867 ;
     RECT  36.912 2.245 36.936 2.915 ;
     RECT  20.016 2.245 20.04 3.059 ;
     RECT  54.144 2.245 54.168 3.107 ;
     RECT  7.8 2.151 8.112 3.301 ;
     RECT  34.8 2.151 35.112 3.301 ;
     RECT  45.6 2.151 45.912 3.301 ;
     RECT  24 2.151 24.312 3.349 ;
     RECT  39.12 1.763 39.144 3.397 ;
     RECT  40.2 2.245 41.304 3.397 ;
     RECT  55.392 3.205 55.416 3.397 ;
     RECT  25.728 2.821 26.52 3.443 ;
     RECT  39.12 3.397 41.304 3.443 ;
     RECT  48.192 2.245 48.216 3.875 ;
     RECT  44.688 3.301 45.912 3.877 ;
     RECT  2.4 2.151 2.712 3.925 ;
     RECT  13.2 2.151 13.512 3.925 ;
     RECT  21.6 2.821 21.624 3.973 ;
     RECT  18.144 2.245 18.912 4.019 ;
     RECT  61.248 2.485 62.112 4.019 ;
     RECT  12.24 3.925 13.512 4.117 ;
     RECT  5.52 3.925 5.544 4.307 ;
     RECT  55.152 3.397 55.416 4.405 ;
     RECT  56.4 2.867 56.712 4.405 ;
     RECT  44.448 3.877 46.776 4.501 ;
     RECT  12.24 4.117 14.28 4.595 ;
     RECT  42.72 3.397 42.744 4.595 ;
     RECT  15.84 3.397 15.864 4.643 ;
     RECT  2.4 3.925 2.904 4.691 ;
     RECT  44.016 4.501 46.776 4.739 ;
     RECT  27.552 2.293 27.576 4.883 ;
     RECT  33.024 2.245 33.048 4.979 ;
     RECT  18.6 4.019 18.912 4.981 ;
     RECT  55.152 4.405 56.712 5.077 ;
     RECT  23.328 3.349 24.312 5.173 ;
     RECT  34.8 3.301 36.024 5.173 ;
     RECT  49.536 4.261 49.56 5.219 ;
     RECT  21.6 3.973 21.672 5.221 ;
     RECT  13.104 4.595 14.28 5.411 ;
     RECT  23.328 5.173 24.456 5.459 ;
     RECT  10.032 4.549 10.056 5.747 ;
     RECT  18.24 4.981 18.912 5.747 ;
     RECT  4.944 5.605 4.968 5.749 ;
     RECT  44.016 4.739 46.152 5.795 ;
     RECT  13.104 5.411 13.512 6.229 ;
     RECT  39.12 3.443 40.512 6.229 ;
     RECT  50.688 2.341 51.312 6.229 ;
     RECT  26.496 3.443 26.52 6.275 ;
     RECT  52.416 4.693 52.44 6.275 ;
     RECT  54.288 5.077 56.712 6.275 ;
     RECT  24 5.459 24.456 6.323 ;
     RECT  32.976 5.077 33 6.323 ;
     RECT  54.288 6.275 54.312 6.323 ;
     RECT  4.944 5.749 5.592 6.563 ;
     RECT  21.408 5.221 21.672 6.563 ;
     RECT  34.8 5.173 36.312 6.611 ;
     RECT  48.288 6.325 48.312 6.661 ;
     RECT  47.472 6.661 48.312 6.851 ;
     RECT  7.8 3.301 8.232 6.899 ;
     RECT  50.352 6.229 51.312 6.899 ;
     RECT  32.784 6.853 32.808 6.995 ;
     RECT  60.192 5.125 60.216 7.043 ;
     RECT  21.648 6.563 21.672 7.091 ;
     RECT  27.6 6.133 27.624 7.091 ;
     RECT  48.288 6.851 48.312 7.379 ;
     RECT  2.4 4.691 2.712 7.429 ;
     RECT  4.944 6.563 4.968 7.429 ;
     RECT  15.36 5.365 15.384 7.765 ;
     RECT  44.016 5.795 45.912 8.003 ;
     RECT  2.4 7.429 2.904 8.195 ;
     RECT  52.848 7.285 52.872 8.291 ;
     RECT  7.8 6.899 8.112 8.437 ;
     RECT  55.536 6.275 56.712 8.437 ;
     RECT  38.88 6.229 40.512 8.485 ;
     RECT  20.784 7.909 20.808 8.531 ;
     RECT  14.64 7.765 15.384 8.579 ;
     RECT  42.864 8.437 42.888 8.677 ;
     RECT  44.448 8.003 45.912 8.677 ;
     RECT  12.864 6.229 13.512 8.723 ;
     RECT  50.88 6.899 51.312 8.723 ;
     RECT  24 6.323 24.312 8.725 ;
     RECT  24 8.725 24.408 9.011 ;
     RECT  44.448 8.677 46.008 9.061 ;
     RECT  55.344 8.437 56.712 9.061 ;
     RECT  7.8 8.437 8.52 9.107 ;
     RECT  13.104 8.723 13.512 9.155 ;
     RECT  31.776 7.909 31.8 9.155 ;
     RECT  34.8 6.611 36.024 9.155 ;
     RECT  58.848 7.765 58.872 9.155 ;
     RECT  55.344 9.061 56.808 9.157 ;
     RECT  44.016 9.061 46.008 9.205 ;
     RECT  44.016 9.205 46.68 9.253 ;
     RECT  43.872 9.253 46.68 9.493 ;
     RECT  54.144 7.909 54.168 9.589 ;
     RECT  55.344 9.157 57.096 9.589 ;
     RECT  54.144 9.589 57.096 9.635 ;
     RECT  26.448 7.621 26.472 9.637 ;
     RECT  38.208 8.485 40.512 9.637 ;
     RECT  26.208 9.637 26.472 9.683 ;
     RECT  17.424 9.253 17.448 9.779 ;
     RECT  51 8.723 51.312 9.925 ;
     RECT  49.008 9.877 49.032 9.973 ;
     RECT  49.008 9.973 49.128 10.019 ;
     RECT  54.672 9.635 57.096 10.165 ;
     RECT  4.512 7.429 4.968 10.355 ;
     RECT  54.672 10.165 58.056 10.597 ;
     RECT  43.872 9.493 47.352 10.835 ;
     RECT  4.512 10.355 4.92 10.883 ;
     RECT  33.216 10.165 33.24 10.883 ;
     RECT  38.208 9.637 41.064 10.883 ;
     RECT  42.768 8.677 42.888 11.077 ;
     RECT  43.872 10.835 46.728 11.077 ;
     RECT  49.104 10.019 49.128 11.171 ;
     RECT  51 9.925 52.2 11.269 ;
     RECT  54.672 10.597 58.344 11.509 ;
     RECT  54.672 11.509 58.392 11.555 ;
     RECT  38.448 10.883 41.064 11.797 ;
     RECT  50.592 11.269 52.2 11.845 ;
     RECT  53.52 11.701 53.544 11.845 ;
     RECT  42.768 11.077 46.728 12.037 ;
     RECT  42.768 12.037 46.776 12.083 ;
     RECT  54.672 11.555 56.712 12.083 ;
     RECT  34.8 9.155 35.976 12.179 ;
     RECT  61.8 4.019 62.112 12.325 ;
     RECT  38.448 11.797 41.688 12.371 ;
     RECT  15.36 8.579 15.384 12.373 ;
     RECT  29.4 2.151 29.712 12.517 ;
     RECT  38.448 12.371 41.064 12.611 ;
     RECT  37.056 10.885 37.08 12.709 ;
     RECT  37.056 12.709 37.224 12.901 ;
     RECT  38.448 12.611 40.512 12.901 ;
     RECT  43.2 12.083 46.776 12.949 ;
     RECT  50.592 11.845 53.544 12.949 ;
     RECT  50.592 12.949 54.12 12.995 ;
     RECT  58.032 11.555 58.392 13.043 ;
     RECT  20.448 12.517 20.472 13.045 ;
     RECT  55.344 12.083 56.712 13.045 ;
     RECT  43.2 12.949 46.872 13.093 ;
     RECT  20.448 13.045 21.384 13.139 ;
     RECT  49.152 11.893 49.176 13.189 ;
     RECT  6.24 12.469 6.264 13.235 ;
     RECT  14.688 12.373 15.384 13.235 ;
     RECT  52.656 12.995 54.12 13.235 ;
     RECT  49.056 13.189 49.176 13.237 ;
     RECT  37.056 12.901 40.512 13.331 ;
     RECT  54.096 13.235 54.12 13.477 ;
     RECT  55.296 13.045 56.712 13.477 ;
     RECT  20.496 13.139 21.384 13.573 ;
     RECT  49.056 13.237 49.272 13.573 ;
     RECT  54.096 13.477 56.712 13.621 ;
     RECT  34.8 12.179 35.88 13.669 ;
     RECT  9.168 13.093 9.192 13.715 ;
     RECT  43.2 13.093 47.496 13.715 ;
     RECT  47.472 13.715 47.496 13.813 ;
     RECT  43.2 13.715 46.44 13.859 ;
     RECT  54.096 13.621 56.856 13.861 ;
     RECT  58.032 13.043 58.056 13.861 ;
     RECT  47.472 13.813 47.88 14.003 ;
     RECT  43.2 13.859 43.224 14.053 ;
     RECT  10.416 10.501 10.44 14.099 ;
     RECT  47.856 14.003 47.88 14.101 ;
     RECT  49.056 13.573 49.416 14.101 ;
     RECT  37.92 13.331 40.512 14.147 ;
     RECT  47.856 14.101 49.416 14.147 ;
     RECT  28.752 12.517 29.712 14.149 ;
     RECT  31.2 13.861 31.224 14.149 ;
     RECT  34.8 13.669 36.264 14.195 ;
     RECT  15.36 13.235 15.384 14.197 ;
     RECT  26.208 9.683 26.232 14.197 ;
     RECT  28.752 14.149 31.224 14.197 ;
     RECT  54.096 13.861 58.056 14.197 ;
     RECT  52.656 13.235 52.68 14.243 ;
     RECT  20.496 13.573 22.248 14.291 ;
     RECT  7.8 9.107 8.112 14.389 ;
     RECT  44.496 13.859 46.44 14.531 ;
     RECT  47.904 14.147 49.416 14.531 ;
     RECT  52.944 14.389 52.968 14.531 ;
     RECT  14.88 14.197 15.384 14.579 ;
     RECT  47.904 14.531 49.032 14.675 ;
     RECT  42.672 14.053 43.224 14.677 ;
     RECT  59.952 13.285 59.976 14.677 ;
     RECT  44.496 14.531 46.008 14.771 ;
     RECT  25.296 14.197 26.232 14.867 ;
     RECT  26.208 14.867 26.232 14.869 ;
     RECT  26.208 14.869 26.52 14.915 ;
     RECT  28.512 14.197 31.224 14.915 ;
     RECT  54.096 14.197 58.152 15.011 ;
     RECT  38.208 14.147 40.512 15.109 ;
     RECT  54.816 15.011 58.152 15.157 ;
     RECT  47.904 14.675 48.552 15.205 ;
     RECT  38.208 15.109 41.064 15.251 ;
     RECT  36.864 14.389 37.08 15.299 ;
     RECT  20.496 14.291 21.384 15.443 ;
     RECT  7.8 14.389 8.616 15.491 ;
     RECT  44.496 14.771 45.912 15.493 ;
     RECT  18.6 5.747 18.912 15.685 ;
     RECT  54.816 15.157 58.44 15.781 ;
     RECT  59.856 14.677 59.976 15.781 ;
     RECT  44.304 15.493 45.912 15.829 ;
     RECT  47.328 15.205 48.552 15.829 ;
     RECT  49.584 15.541 49.608 15.829 ;
     RECT  33.408 14.773 33.432 16.019 ;
     RECT  34.8 14.195 35.88 16.019 ;
     RECT  29.4 14.915 31.224 16.067 ;
     RECT  54.816 15.781 59.976 16.115 ;
     RECT  13.2 9.155 13.512 16.117 ;
     RECT  38.208 15.251 40.512 16.213 ;
     RECT  42.624 14.677 43.224 16.213 ;
     RECT  42.576 16.213 43.224 16.405 ;
     RECT  44.304 15.829 49.608 16.405 ;
     RECT  58.416 16.115 59.976 16.453 ;
     RECT  16.08 15.349 16.104 16.547 ;
     RECT  42.576 16.405 49.608 16.547 ;
     RECT  38.208 16.213 41.112 16.549 ;
     RECT  42.576 16.547 43.032 16.549 ;
     RECT  18.48 15.685 18.912 16.595 ;
     RECT  7.8 15.491 8.112 16.645 ;
     RECT  37.056 15.299 37.08 16.645 ;
     RECT  38.208 16.549 43.032 16.645 ;
     RECT  50.592 12.995 51.312 16.645 ;
     RECT  37.056 16.645 43.032 16.691 ;
     RECT  38.784 16.691 43.032 16.883 ;
     RECT  44.16 16.547 49.608 16.883 ;
     RECT  37.056 16.691 37.608 16.885 ;
     RECT  45.6 16.883 49.608 16.885 ;
     RECT  50.592 16.645 51.432 16.885 ;
     RECT  45.6 16.885 51.432 16.979 ;
     RECT  29.4 16.067 30.6 16.981 ;
     RECT  47.904 16.979 51.432 17.027 ;
     RECT  48.384 17.027 51.432 17.029 ;
     RECT  34.8 16.019 35.832 17.075 ;
     RECT  29.04 16.981 30.6 17.123 ;
     RECT  33.072 16.885 33.096 17.123 ;
     RECT  36.96 16.885 37.608 17.123 ;
     RECT  48.384 17.029 52.152 17.123 ;
     RECT  31.728 16.981 31.752 17.125 ;
     RECT  12.432 16.117 13.512 17.171 ;
     RECT  37.056 17.123 37.608 17.171 ;
     RECT  34.8 17.075 35.544 17.221 ;
     RECT  9.84 17.077 9.864 17.267 ;
     RECT  12.912 17.171 13.512 17.267 ;
     RECT  37.056 17.171 37.512 17.267 ;
     RECT  41.856 16.883 43.032 17.267 ;
     RECT  4.896 10.883 4.92 17.605 ;
     RECT  6.816 16.645 8.112 17.651 ;
     RECT  42.432 17.267 43.032 17.653 ;
     RECT  44.16 16.883 44.568 17.653 ;
     RECT  33.936 17.221 35.544 17.747 ;
     RECT  14.88 14.579 14.904 17.843 ;
     RECT  22.752 16.789 22.776 17.843 ;
     RECT  58.416 16.453 60.024 17.893 ;
     RECT  31.728 17.125 32.136 17.939 ;
     RECT  45.6 16.979 46.776 17.989 ;
     RECT  58.416 17.893 60.504 18.131 ;
     RECT  32.112 17.939 32.136 18.179 ;
     RECT  37.152 17.267 37.512 18.181 ;
     RECT  38.784 16.883 40.632 18.181 ;
     RECT  49.344 17.123 52.152 18.181 ;
     RECT  37.152 18.181 40.632 18.227 ;
     RECT  49.344 18.181 52.44 18.227 ;
     RECT  4.368 17.605 4.92 18.275 ;
     RECT  45.6 17.989 47.496 18.275 ;
     RECT  2.4 8.195 2.712 18.277 ;
     RECT  37.152 18.227 37.176 18.373 ;
     RECT  52.416 18.227 52.44 18.469 ;
     RECT  21.12 15.443 21.384 18.515 ;
     RECT  38.16 18.227 40.632 18.515 ;
     RECT  61.8 12.325 62.328 18.565 ;
     RECT  33.936 17.747 35.448 18.709 ;
     RECT  2.4 18.277 2.856 18.851 ;
     RECT  42.432 17.653 44.568 18.851 ;
     RECT  44.16 18.851 44.568 18.901 ;
     RECT  45.6 18.275 46.776 18.901 ;
     RECT  49.344 18.227 51.312 18.947 ;
     RECT  18.6 16.595 18.912 19.093 ;
     RECT  37.056 18.373 37.176 19.237 ;
     RECT  38.16 18.515 40.512 19.237 ;
     RECT  33.936 18.709 35.736 19.285 ;
     RECT  17.712 19.093 18.912 19.333 ;
     RECT  11.136 18.709 11.16 19.379 ;
     RECT  26.496 14.915 26.52 19.427 ;
     RECT  44.16 18.901 46.776 19.427 ;
     RECT  58.416 18.131 60.024 19.523 ;
     RECT  61.632 18.565 62.328 19.571 ;
     RECT  42.432 18.851 43.032 19.619 ;
     RECT  52.416 18.469 53.304 19.621 ;
     RECT  48.144 18.709 48.168 19.669 ;
     RECT  49.344 18.947 49.464 19.669 ;
     RECT  7.8 17.651 8.112 19.813 ;
     RECT  17.712 19.333 19.416 19.955 ;
     RECT  21.12 18.515 21.144 19.957 ;
     RECT  58.416 19.523 59.208 20.003 ;
     RECT  26.4 19.429 26.424 20.051 ;
     RECT  48.144 19.669 49.464 20.099 ;
     RECT  61.632 19.571 62.112 20.245 ;
     RECT  37.056 19.237 40.512 20.291 ;
     RECT  54.816 16.115 57 20.339 ;
     RECT  58.416 20.003 58.488 20.341 ;
     RECT  55.824 20.339 57 20.387 ;
     RECT  61.584 20.245 62.112 20.387 ;
     RECT  48.24 20.099 49.464 20.389 ;
     RECT  54.816 20.339 54.84 20.435 ;
     RECT  29.4 17.123 30.6 20.485 ;
     RECT  7.8 19.813 8.52 20.579 ;
     RECT  17.712 19.955 18.912 20.579 ;
     RECT  33.072 19.285 35.736 20.579 ;
     RECT  29.4 20.485 31.56 20.581 ;
     RECT  33.072 20.579 33.096 20.581 ;
     RECT  4.752 19.813 4.776 20.627 ;
     RECT  34.08 20.579 35.736 20.627 ;
     RECT  34.8 20.627 35.736 20.677 ;
     RECT  50.832 18.947 51.312 20.677 ;
     RECT  52.416 19.621 53.592 20.677 ;
     RECT  44.16 19.427 46.728 20.723 ;
     RECT  37.056 20.291 37.8 20.819 ;
     RECT  21.12 19.957 21.24 20.821 ;
     RECT  58.272 20.341 58.488 20.867 ;
     RECT  34.8 20.677 35.88 20.869 ;
     RECT  50.832 20.677 53.592 20.963 ;
     RECT  50.832 20.963 51.432 20.965 ;
     RECT  34.8 20.869 36.12 21.011 ;
     RECT  48.24 20.389 49.56 21.011 ;
     RECT  52.512 20.963 53.592 21.011 ;
     RECT  37.152 20.819 37.8 21.059 ;
     RECT  52.896 21.011 53.592 21.109 ;
     RECT  15.84 20.293 15.864 21.155 ;
     RECT  29.4 20.581 33.096 21.155 ;
     RECT  48.24 21.011 48.264 21.155 ;
     RECT  45.6 20.723 46.728 21.157 ;
     RECT  58.272 20.867 58.44 21.203 ;
     RECT  38.784 20.291 40.512 21.253 ;
     RECT  52.896 21.109 54.408 21.299 ;
     RECT  45.6 21.157 46.776 21.347 ;
     RECT  21.12 20.821 21.672 21.395 ;
     RECT  55.824 20.387 56.808 21.395 ;
     RECT  38.784 21.253 40.632 21.589 ;
     RECT  52.896 21.299 53.592 21.635 ;
     RECT  24 9.011 24.312 21.637 ;
     RECT  38.784 21.589 41.064 21.683 ;
     RECT  44.16 20.723 44.376 21.781 ;
     RECT  56.016 21.395 56.808 21.827 ;
     RECT  34.8 21.011 35.88 21.925 ;
     RECT  13.2 17.267 13.512 21.973 ;
     RECT  44.16 21.781 44.472 22.019 ;
     RECT  34.416 21.925 35.88 22.067 ;
     RECT  13.104 21.973 13.512 22.115 ;
     RECT  21.12 21.395 21.144 22.117 ;
     RECT  2.4 18.851 2.712 22.165 ;
     RECT  37.776 21.059 37.8 22.165 ;
     RECT  56.4 21.827 56.808 22.165 ;
     RECT  58.416 21.203 58.44 22.165 ;
     RECT  32.112 21.155 33.096 22.211 ;
     RECT  50.544 20.965 51.432 22.213 ;
     RECT  56.4 22.165 58.44 22.213 ;
     RECT  43.008 19.619 43.032 22.307 ;
     RECT  33.072 22.211 33.096 22.451 ;
     RECT  50.544 22.213 51.576 22.499 ;
     RECT  50.832 22.499 51.576 22.547 ;
     RECT  54.72 22.309 54.744 22.547 ;
     RECT  38.88 21.683 41.064 22.597 ;
     RECT  44.16 22.019 44.376 22.645 ;
     RECT  14.736 21.637 14.76 22.739 ;
     RECT  20.976 22.117 21.144 22.741 ;
     RECT  56.4 22.213 58.68 22.741 ;
     RECT  20.208 22.741 21.144 22.787 ;
     RECT  18.6 20.579 18.912 22.789 ;
     RECT  4.368 22.165 4.392 23.027 ;
     RECT  11.952 22.741 11.976 23.075 ;
     RECT  34.416 22.067 35.688 23.123 ;
     RECT  2.4 22.165 2.808 23.267 ;
     RECT  38.88 22.597 41.352 23.317 ;
     RECT  34.8 23.123 35.688 23.411 ;
     RECT  45.6 21.347 46.728 23.459 ;
     RECT  56.4 22.741 58.968 23.459 ;
     RECT  52.992 21.635 53.592 23.509 ;
     RECT  38.88 23.317 42.168 23.603 ;
     RECT  10.32 19.909 10.344 23.605 ;
     RECT  56.4 23.459 57.624 23.651 ;
     RECT  52.464 23.509 53.592 23.699 ;
     RECT  38.88 23.603 40.632 23.747 ;
     RECT  43.296 22.645 44.376 23.795 ;
     RECT  10.32 23.605 10.872 23.845 ;
     RECT  47.712 22.741 47.736 23.939 ;
     RECT  23.328 21.637 24.312 23.987 ;
     RECT  37.056 22.165 37.8 23.987 ;
     RECT  44.256 23.795 44.376 23.987 ;
     RECT  60.048 22.165 60.072 23.987 ;
     RECT  37.056 23.987 37.08 24.083 ;
     RECT  55.296 22.741 55.32 24.131 ;
     RECT  20.208 22.787 21 24.227 ;
     RECT  29.4 21.155 30.6 24.227 ;
     RECT  9.648 23.845 10.872 24.371 ;
     RECT  24 23.987 24.312 24.469 ;
     RECT  29.4 24.227 30.264 24.515 ;
     RECT  18.48 22.789 18.912 24.563 ;
     RECT  41.616 23.603 42.168 24.611 ;
     RECT  56.4 23.651 56.808 24.757 ;
     RECT  38.88 23.747 40.512 24.803 ;
     RECT  39.888 24.803 40.512 24.947 ;
     RECT  14.88 24.325 14.904 25.045 ;
     RECT  44.256 23.987 44.28 25.045 ;
     RECT  56.304 24.757 56.808 25.045 ;
     RECT  40.2 24.947 40.512 25.093 ;
     RECT  9.648 24.371 9.672 25.139 ;
     RECT  47.904 24.469 47.928 25.141 ;
     RECT  49.344 21.011 49.56 25.141 ;
     RECT  24 24.469 24.936 25.187 ;
     RECT  47.904 25.141 49.56 25.187 ;
     RECT  52.464 23.699 53.4 25.187 ;
     RECT  20.208 24.227 20.568 25.379 ;
     RECT  44.256 25.045 44.424 25.573 ;
     RECT  45.6 23.459 45.912 25.573 ;
     RECT  56.304 25.045 57.576 25.573 ;
     RECT  55.872 25.573 57.576 25.667 ;
     RECT  20.208 25.379 20.232 25.669 ;
     RECT  20.112 25.669 20.232 25.715 ;
     RECT  40.2 25.093 40.632 25.715 ;
     RECT  54.864 24.469 54.888 25.811 ;
     RECT  38.88 24.803 38.904 25.813 ;
     RECT  14.88 25.045 15.384 25.907 ;
     RECT  18.6 24.563 18.912 26.005 ;
     RECT  38.496 25.813 38.904 26.053 ;
     RECT  29.4 24.515 29.712 26.101 ;
     RECT  50.832 22.547 51.312 26.197 ;
     RECT  21.696 25.477 21.72 26.243 ;
     RECT  48.576 25.187 49.56 26.243 ;
     RECT  10.848 24.371 10.872 26.291 ;
     RECT  38.208 26.053 38.904 26.291 ;
     RECT  6.288 24.469 6.312 26.293 ;
     RECT  6.288 26.293 6.648 26.339 ;
     RECT  48.576 26.243 48.6 26.579 ;
     RECT  44.256 25.573 45.912 26.629 ;
     RECT  29.4 26.101 30.6 26.675 ;
     RECT  57.744 26.725 57.768 26.773 ;
     RECT  58.944 23.459 58.968 26.773 ;
     RECT  20.112 25.715 20.136 26.819 ;
     RECT  37.056 26.005 37.08 26.819 ;
     RECT  55.872 25.667 56.712 26.819 ;
     RECT  26.064 22.405 26.088 27.061 ;
     RECT  26.064 27.061 26.232 27.107 ;
     RECT  52.464 25.187 52.488 27.155 ;
     RECT  57.744 26.773 58.968 27.251 ;
     RECT  41.616 24.611 41.64 27.299 ;
     RECT  13.2 22.115 13.512 27.349 ;
     RECT  6.624 26.339 6.648 27.395 ;
     RECT  43.632 26.629 45.912 27.443 ;
     RECT  18.48 26.005 18.912 27.635 ;
     RECT  5.184 23.173 5.208 27.733 ;
     RECT  50.592 26.197 51.312 27.733 ;
     RECT  26.208 27.107 26.232 27.781 ;
     RECT  9.6 26.725 9.624 27.827 ;
     RECT  26.208 27.781 26.904 27.827 ;
     RECT  40.2 25.715 40.512 27.877 ;
     RECT  15.168 25.907 15.384 27.923 ;
     RECT  26.4 27.827 26.904 27.923 ;
     RECT  15.36 27.923 15.384 27.971 ;
     RECT  29.4 26.675 30.264 27.971 ;
     RECT  57.744 27.251 57.768 27.971 ;
     RECT  29.4 27.971 29.712 28.261 ;
     RECT  47.568 27.301 47.592 28.451 ;
     RECT  13.2 27.349 13.656 28.691 ;
     RECT  43.632 27.443 43.656 28.739 ;
     RECT  18.6 27.635 18.912 28.741 ;
     RECT  56.064 26.819 56.712 28.741 ;
     RECT  53.664 27.301 53.688 28.789 ;
     RECT  10.8 27.781 10.824 28.835 ;
     RECT  2.4 23.267 2.712 28.837 ;
     RECT  7.8 20.579 8.112 28.981 ;
     RECT  21.6 26.581 21.624 28.981 ;
     RECT  4.704 27.733 5.208 29.027 ;
     RECT  4.704 29.027 4.728 29.075 ;
     RECT  45.024 27.443 45.912 29.123 ;
     RECT  20.88 28.981 21.624 29.363 ;
     RECT  26.4 27.923 26.424 29.507 ;
     RECT  56.064 28.741 57 29.555 ;
     RECT  2.4 28.837 2.856 29.605 ;
     RECT  18.6 28.741 19.272 29.699 ;
     RECT  37.008 28.501 37.032 29.747 ;
     RECT  12 29.509 12.024 29.795 ;
     RECT  52.464 28.741 52.488 29.795 ;
     RECT  0.144 29.029 0.168 29.797 ;
     RECT  58.944 27.251 58.968 29.989 ;
     RECT  58.752 29.989 58.968 30.035 ;
     RECT  53.664 28.789 54.264 30.037 ;
     RECT  52.992 30.037 54.264 30.083 ;
     RECT  2.4 29.605 3.672 30.227 ;
     RECT  29.04 28.261 29.712 30.227 ;
     RECT  45.6 29.123 45.912 30.229 ;
     RECT  0.144 29.797 0.216 30.419 ;
     RECT  52.992 30.083 53.688 30.467 ;
     RECT  56.064 29.555 56.712 30.611 ;
     RECT  40.2 27.877 40.632 30.757 ;
     RECT  52.992 30.467 53.016 30.803 ;
     RECT  59.856 30.709 59.88 30.851 ;
     RECT  42.72 30.757 42.744 30.899 ;
     RECT  0.192 30.419 0.216 30.995 ;
     RECT  21.6 29.363 21.624 31.285 ;
     RECT  21.456 31.285 21.624 31.333 ;
     RECT  50.16 27.733 51.312 31.525 ;
     RECT  50.16 31.525 51.864 31.765 ;
     RECT  50.16 31.765 52.056 31.811 ;
     RECT  38.208 26.291 38.232 31.813 ;
     RECT  38.208 31.813 38.76 31.859 ;
     RECT  2.4 30.227 3.096 31.861 ;
     RECT  18.6 29.699 18.912 31.909 ;
     RECT  20.208 30.037 20.232 31.955 ;
     RECT  40.2 30.757 40.68 32.149 ;
     RECT  25.68 30.997 25.704 32.195 ;
     RECT  21.456 31.333 22.248 32.197 ;
     RECT  13.2 28.691 13.512 32.293 ;
     RECT  58.752 30.035 58.776 32.293 ;
     RECT  20.544 32.197 22.248 32.339 ;
     RECT  34.8 23.411 35.112 32.437 ;
     RECT  58.752 32.293 58.968 32.437 ;
     RECT  50.832 31.811 52.056 32.483 ;
     RECT  21.456 32.339 22.248 32.531 ;
     RECT  50.832 32.483 51.864 32.531 ;
     RECT  54.096 31.525 54.12 32.627 ;
     RECT  9.648 32.005 9.672 32.725 ;
     RECT  34.8 32.437 35.208 32.725 ;
     RECT  9.12 32.725 9.672 32.867 ;
     RECT  33.072 32.629 33.096 32.867 ;
     RECT  34.704 32.725 35.208 32.915 ;
     RECT  18.432 31.909 18.912 33.013 ;
     RECT  45.504 30.229 45.912 33.013 ;
     RECT  13.104 32.293 13.512 33.059 ;
     RECT  58.032 32.437 58.968 33.107 ;
     RECT  17.856 33.013 18.912 33.109 ;
     RECT  9.216 32.867 9.672 33.299 ;
     RECT  31.296 30.421 31.32 33.443 ;
     RECT  5.28 32.581 5.304 33.635 ;
     RECT  2.4 31.861 3.432 33.683 ;
     RECT  34.8 32.915 35.208 33.779 ;
     RECT  42.768 33.637 42.792 33.875 ;
     RECT  13.2 33.059 13.512 34.021 ;
     RECT  22.752 33.205 22.776 34.069 ;
     RECT  24 25.187 24.312 34.069 ;
     RECT  40.2 32.149 40.872 34.211 ;
     RECT  45.312 33.013 45.912 34.211 ;
     RECT  0.144 32.389 0.168 34.259 ;
     RECT  15.648 33.589 15.672 34.309 ;
     RECT  15.552 34.309 15.672 34.355 ;
     RECT  13.2 34.021 13.608 34.403 ;
     RECT  15.552 34.355 15.576 34.451 ;
     RECT  34.8 33.779 35.112 34.453 ;
     RECT  50.832 32.531 51.312 34.741 ;
     RECT  9.216 33.299 9.24 34.835 ;
     RECT  50.832 34.741 52.008 34.835 ;
     RECT  22.752 34.069 24.312 34.883 ;
     RECT  23.472 34.883 24.312 35.171 ;
     RECT  21.456 32.531 21.48 35.173 ;
     RECT  34.224 34.453 35.112 35.315 ;
     RECT  17.664 33.109 18.912 35.317 ;
     RECT  50.88 34.835 52.008 35.317 ;
     RECT  16.8 35.317 18.912 35.363 ;
     RECT  40.2 34.211 40.632 35.363 ;
     RECT  50.88 35.317 52.488 35.363 ;
     RECT  54.72 34.117 54.744 35.363 ;
     RECT  58.944 33.107 58.968 35.365 ;
     RECT  58.656 35.365 58.968 35.507 ;
     RECT  24 35.171 24.312 35.749 ;
     RECT  29.4 30.227 29.712 35.845 ;
     RECT  31.104 34.021 31.128 35.845 ;
     RECT  7.632 28.981 8.112 35.941 ;
     RECT  49.392 35.317 49.416 35.987 ;
     RECT  13.2 34.403 13.512 35.989 ;
     RECT  24 35.749 24.504 36.083 ;
     RECT  13.2 35.989 13.608 36.277 ;
     RECT  56.4 30.611 56.712 36.421 ;
     RECT  25.632 35.845 25.656 36.563 ;
     RECT  21.072 35.173 21.48 36.613 ;
     RECT  18.6 35.363 18.912 36.709 ;
     RECT  19.92 35.269 19.944 36.709 ;
     RECT  52.464 35.363 52.488 36.755 ;
     RECT  16.8 35.363 16.824 36.805 ;
     RECT  18.6 36.709 19.944 36.805 ;
     RECT  36.864 34.789 36.888 36.851 ;
     RECT  16.8 36.805 19.944 36.947 ;
     RECT  20.976 36.613 21.48 36.995 ;
     RECT  21.456 36.995 21.48 36.997 ;
     RECT  55.008 36.421 55.032 36.997 ;
     RECT  56.4 36.421 57.48 36.997 ;
     RECT  34.56 35.315 35.112 37.043 ;
     RECT  38.736 31.859 38.76 37.045 ;
     RECT  19.92 36.947 19.944 37.091 ;
     RECT  55.008 36.997 57.48 37.091 ;
     RECT  7.44 35.941 8.112 37.141 ;
     RECT  7.44 37.141 8.568 37.187 ;
     RECT  13.104 36.277 13.608 37.187 ;
     RECT  32.256 37.045 33.096 37.187 ;
     RECT  38.736 37.045 39.144 37.187 ;
     RECT  55.584 37.091 57.48 37.283 ;
     RECT  7.8 37.187 8.568 37.285 ;
     RECT  40.2 35.363 40.512 37.285 ;
     RECT  16.8 36.947 18.912 37.331 ;
     RECT  43.584 35.413 43.608 37.379 ;
     RECT  13.104 37.187 13.512 37.427 ;
     RECT  40.2 37.285 40.632 37.429 ;
     RECT  61.8 20.387 62.112 37.429 ;
     RECT  24 36.083 24.312 37.573 ;
     RECT  17.04 37.331 18.912 37.715 ;
     RECT  21.456 36.997 21.96 38.003 ;
     RECT  21.456 38.003 21.48 38.101 ;
     RECT  29.4 35.845 31.128 38.147 ;
     RECT  11.04 36.997 11.064 38.243 ;
     RECT  50.88 35.363 51.312 38.243 ;
     RECT  58.944 35.507 58.968 38.243 ;
     RECT  7.8 37.285 8.904 38.387 ;
     RECT  55.584 37.283 56.712 38.675 ;
     RECT  40.2 37.429 40.68 38.723 ;
     RECT  60.96 37.429 62.112 38.771 ;
     RECT  32.256 37.187 32.28 38.819 ;
     RECT  21.12 38.101 21.48 39.107 ;
     RECT  59.376 38.725 59.832 39.107 ;
     RECT  38.736 37.187 38.76 39.251 ;
     RECT  40.2 38.723 40.632 39.251 ;
     RECT  45.6 34.211 45.912 39.301 ;
     RECT  51 38.243 51.312 39.301 ;
     RECT  24 37.573 24.504 39.347 ;
     RECT  52.848 38.341 52.872 39.589 ;
     RECT  52.464 39.589 52.872 39.635 ;
     RECT  10.512 38.581 10.536 39.827 ;
     RECT  21.408 39.107 21.48 40.067 ;
     RECT  42.864 39.253 42.888 40.067 ;
     RECT  33.648 38.677 33.672 40.451 ;
     RECT  37.632 39.829 37.656 40.499 ;
     RECT  45.6 39.301 46.008 40.499 ;
     RECT  50.496 39.301 51.312 40.499 ;
     RECT  52.464 39.635 52.488 40.595 ;
     RECT  17.04 37.715 17.064 40.835 ;
     RECT  21.408 40.067 21.432 40.835 ;
     RECT  40.2 39.251 40.512 40.837 ;
     RECT  59.376 39.107 59.4 40.883 ;
     RECT  2.4 33.683 2.712 41.049 ;
     RECT  7.8 38.387 8.112 41.049 ;
     RECT  13.2 37.427 13.512 41.049 ;
     RECT  18.6 37.715 18.912 41.049 ;
     RECT  24 39.347 24.312 41.049 ;
     RECT  29.4 38.147 29.712 41.049 ;
     RECT  34.8 37.043 35.112 41.049 ;
     RECT  45.6 40.499 45.912 41.049 ;
     RECT  51 40.499 51.312 41.049 ;
     RECT  56.4 38.675 56.712 41.049 ;
     RECT  61.8 38.771 62.112 41.049 ;
     RECT  2.4 41.049 2.52 41.063 ;
     RECT  7.8 41.049 7.92 41.063 ;
     RECT  13.2 41.049 13.32 41.063 ;
     RECT  18.6 41.049 18.72 41.063 ;
     RECT  24 41.049 24.12 41.063 ;
     RECT  29.4 41.049 29.52 41.063 ;
     RECT  34.8 41.049 34.92 41.063 ;
     RECT  45.6 41.049 45.72 41.063 ;
     RECT  51 41.049 51.12 41.063 ;
     RECT  56.4 41.049 56.52 41.063 ;
     RECT  61.8 41.049 61.92 41.063 ;
     RECT  39.696 40.837 40.512 41.125 ;
     RECT  39.696 41.125 40.584 42.997 ;
     RECT  39.504 42.997 40.584 43.139 ;
     RECT  39.6 43.139 40.584 43.152 ;
  END
END dsfd_svc_join
END LIBRARY
